VERSION 5.8 ;
BUSBITCHARS "[]" ;
DIVIDERCHAR "/" ;
UNITS
    DATABASE MICRONS 1000 ;
END UNITS

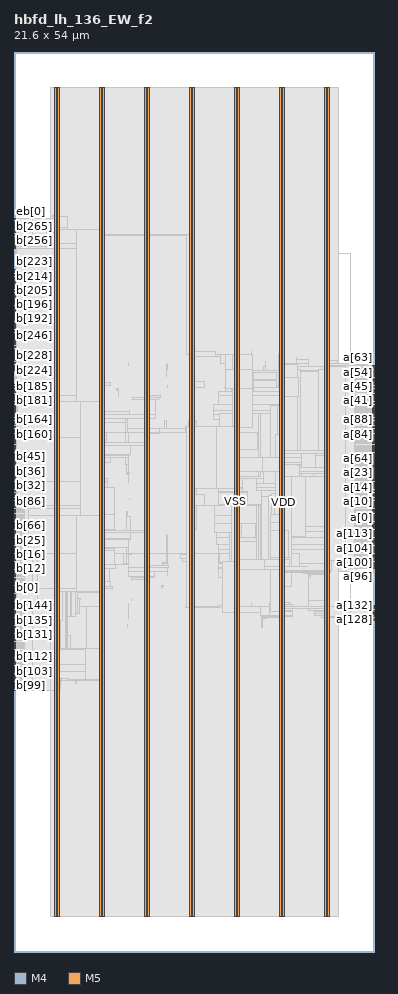
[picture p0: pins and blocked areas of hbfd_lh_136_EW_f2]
MACRO hbfd_lh_136_EW_f2
  FOREIGN hbfd_lh_136_EW_f2 0 0 ;
  CLASS BLOCK ;
  SIZE 21.6 BY 54 ;
  PIN a[0]
    DIRECTION INPUT ;
    USE SIGNAL ;
    PORT
      LAYER M4 ;
        RECT  21.516 26.064 21.6 26.088 ;
    END
  END a[0]
  PIN a[100]
    DIRECTION INPUT ;
    USE SIGNAL ;
    PORT
      LAYER M4 ;
        RECT  21.516 23.376 21.6 23.4 ;
    END
  END a[100]
  PIN a[101]
    DIRECTION INPUT ;
    USE SIGNAL ;
    PORT
      LAYER M4 ;
        RECT  21.516 23.472 21.6 23.496 ;
    END
  END a[101]
  PIN a[102]
    DIRECTION INPUT ;
    USE SIGNAL ;
    PORT
      LAYER M4 ;
        RECT  21.516 23.568 21.6 23.592 ;
    END
  END a[102]
  PIN a[103]
    DIRECTION INPUT ;
    USE SIGNAL ;
    PORT
      LAYER M4 ;
        RECT  21.516 23.664 21.6 23.688 ;
    END
  END a[103]
  PIN a[104]
    DIRECTION INPUT ;
    USE SIGNAL ;
    PORT
      LAYER M4 ;
        RECT  21.516 23.76 21.6 23.784 ;
    END
  END a[104]
  PIN a[105]
    DIRECTION INPUT ;
    USE SIGNAL ;
    PORT
      LAYER M4 ;
        RECT  21.516 23.856 21.6 23.88 ;
    END
  END a[105]
  PIN a[106]
    DIRECTION INPUT ;
    USE SIGNAL ;
    PORT
      LAYER M4 ;
        RECT  21.516 23.952 21.6 23.976 ;
    END
  END a[106]
  PIN a[107]
    DIRECTION INPUT ;
    USE SIGNAL ;
    PORT
      LAYER M4 ;
        RECT  21.516 24.048 21.6 24.072 ;
    END
  END a[107]
  PIN a[108]
    DIRECTION INPUT ;
    USE SIGNAL ;
    PORT
      LAYER M4 ;
        RECT  21.516 24.144 21.6 24.168 ;
    END
  END a[108]
  PIN a[109]
    DIRECTION INPUT ;
    USE SIGNAL ;
    PORT
      LAYER M4 ;
        RECT  21.516 24.24 21.6 24.264 ;
    END
  END a[109]
  PIN a[10]
    DIRECTION INPUT ;
    USE SIGNAL ;
    PORT
      LAYER M4 ;
        RECT  21.516 27.024 21.6 27.048 ;
    END
  END a[10]
  PIN a[110]
    DIRECTION INPUT ;
    USE SIGNAL ;
    PORT
      LAYER M4 ;
        RECT  21.516 24.336 21.6 24.36 ;
    END
  END a[110]
  PIN a[111]
    DIRECTION INPUT ;
    USE SIGNAL ;
    PORT
      LAYER M4 ;
        RECT  21.516 24.432 21.6 24.456 ;
    END
  END a[111]
  PIN a[112]
    DIRECTION INPUT ;
    USE SIGNAL ;
    PORT
      LAYER M4 ;
        RECT  21.516 24.528 21.6 24.552 ;
    END
  END a[112]
  PIN a[113]
    DIRECTION INPUT ;
    USE SIGNAL ;
    PORT
      LAYER M4 ;
        RECT  21.516 24.624 21.6 24.648 ;
    END
  END a[113]
  PIN a[114]
    DIRECTION INPUT ;
    USE SIGNAL ;
    PORT
      LAYER M4 ;
        RECT  21.516 24.72 21.6 24.744 ;
    END
  END a[114]
  PIN a[115]
    DIRECTION INPUT ;
    USE SIGNAL ;
    PORT
      LAYER M4 ;
        RECT  21.516 24.816 21.6 24.84 ;
    END
  END a[115]
  PIN a[116]
    DIRECTION INPUT ;
    USE SIGNAL ;
    PORT
      LAYER M4 ;
        RECT  21.516 24.912 21.6 24.936 ;
    END
  END a[116]
  PIN a[117]
    DIRECTION INPUT ;
    USE SIGNAL ;
    PORT
      LAYER M4 ;
        RECT  21.516 25.008 21.6 25.032 ;
    END
  END a[117]
  PIN a[118]
    DIRECTION INPUT ;
    USE SIGNAL ;
    PORT
      LAYER M4 ;
        RECT  21.516 25.104 21.6 25.128 ;
    END
  END a[118]
  PIN a[119]
    DIRECTION INPUT ;
    USE SIGNAL ;
    PORT
      LAYER M4 ;
        RECT  21.516 25.2 21.6 25.224 ;
    END
  END a[119]
  PIN a[11]
    DIRECTION INPUT ;
    USE SIGNAL ;
    PORT
      LAYER M4 ;
        RECT  21.516 27.12 21.6 27.144 ;
    END
  END a[11]
  PIN a[120]
    DIRECTION INPUT ;
    USE SIGNAL ;
    PORT
      LAYER M4 ;
        RECT  21.516 25.296 21.6 25.32 ;
    END
  END a[120]
  PIN a[121]
    DIRECTION INPUT ;
    USE SIGNAL ;
    PORT
      LAYER M4 ;
        RECT  21.516 25.392 21.6 25.416 ;
    END
  END a[121]
  PIN a[122]
    DIRECTION INPUT ;
    USE SIGNAL ;
    PORT
      LAYER M4 ;
        RECT  21.516 25.488 21.6 25.512 ;
    END
  END a[122]
  PIN a[123]
    DIRECTION INPUT ;
    USE SIGNAL ;
    PORT
      LAYER M4 ;
        RECT  21.516 25.584 21.6 25.608 ;
    END
  END a[123]
  PIN a[124]
    DIRECTION INPUT ;
    USE SIGNAL ;
    PORT
      LAYER M4 ;
        RECT  21.516 25.68 21.6 25.704 ;
    END
  END a[124]
  PIN a[125]
    DIRECTION INPUT ;
    USE SIGNAL ;
    PORT
      LAYER M4 ;
        RECT  21.516 25.776 21.6 25.8 ;
    END
  END a[125]
  PIN a[126]
    DIRECTION INPUT ;
    USE SIGNAL ;
    PORT
      LAYER M4 ;
        RECT  21.516 25.872 21.6 25.896 ;
    END
  END a[126]
  PIN a[127]
    DIRECTION INPUT ;
    USE SIGNAL ;
    PORT
      LAYER M4 ;
        RECT  21.516 25.968 21.6 25.992 ;
    END
  END a[127]
  PIN a[128]
    DIRECTION INPUT ;
    USE SIGNAL ;
    PORT
      LAYER M4 ;
        RECT  21.516 19.92 21.6 19.944 ;
    END
  END a[128]
  PIN a[129]
    DIRECTION INPUT ;
    USE SIGNAL ;
    PORT
      LAYER M4 ;
        RECT  21.516 20.016 21.6 20.04 ;
    END
  END a[129]
  PIN a[12]
    DIRECTION INPUT ;
    USE SIGNAL ;
    PORT
      LAYER M4 ;
        RECT  21.516 27.216 21.6 27.24 ;
    END
  END a[12]
  PIN a[130]
    DIRECTION INPUT ;
    USE SIGNAL ;
    PORT
      LAYER M4 ;
        RECT  21.516 20.112 21.6 20.136 ;
    END
  END a[130]
  PIN a[131]
    DIRECTION INPUT ;
    USE SIGNAL ;
    PORT
      LAYER M4 ;
        RECT  21.516 20.208 21.6 20.232 ;
    END
  END a[131]
  PIN a[132]
    DIRECTION INPUT ;
    USE SIGNAL ;
    PORT
      LAYER M4 ;
        RECT  21.516 20.304 21.6 20.328 ;
    END
  END a[132]
  PIN a[133]
    DIRECTION INPUT ;
    USE SIGNAL ;
    PORT
      LAYER M4 ;
        RECT  21.516 20.4 21.6 20.424 ;
    END
  END a[133]
  PIN a[134]
    DIRECTION INPUT ;
    USE SIGNAL ;
    PORT
      LAYER M4 ;
        RECT  21.516 20.496 21.6 20.52 ;
    END
  END a[134]
  PIN a[135]
    DIRECTION INPUT ;
    USE SIGNAL ;
    PORT
      LAYER M4 ;
        RECT  21.516 20.592 21.6 20.616 ;
    END
  END a[135]
  PIN a[13]
    DIRECTION INPUT ;
    USE SIGNAL ;
    PORT
      LAYER M4 ;
        RECT  21.516 27.312 21.6 27.336 ;
    END
  END a[13]
  PIN a[14]
    DIRECTION INPUT ;
    USE SIGNAL ;
    PORT
      LAYER M4 ;
        RECT  21.516 27.408 21.6 27.432 ;
    END
  END a[14]
  PIN a[15]
    DIRECTION INPUT ;
    USE SIGNAL ;
    PORT
      LAYER M4 ;
        RECT  21.516 27.504 21.6 27.528 ;
    END
  END a[15]
  PIN a[16]
    DIRECTION INPUT ;
    USE SIGNAL ;
    PORT
      LAYER M4 ;
        RECT  21.516 27.6 21.6 27.624 ;
    END
  END a[16]
  PIN a[17]
    DIRECTION INPUT ;
    USE SIGNAL ;
    PORT
      LAYER M4 ;
        RECT  21.516 27.696 21.6 27.72 ;
    END
  END a[17]
  PIN a[18]
    DIRECTION INPUT ;
    USE SIGNAL ;
    PORT
      LAYER M4 ;
        RECT  21.516 27.792 21.6 27.816 ;
    END
  END a[18]
  PIN a[19]
    DIRECTION INPUT ;
    USE SIGNAL ;
    PORT
      LAYER M4 ;
        RECT  21.516 27.888 21.6 27.912 ;
    END
  END a[19]
  PIN a[1]
    DIRECTION INPUT ;
    USE SIGNAL ;
    PORT
      LAYER M4 ;
        RECT  21.516 26.16 21.6 26.184 ;
    END
  END a[1]
  PIN a[20]
    DIRECTION INPUT ;
    USE SIGNAL ;
    PORT
      LAYER M4 ;
        RECT  21.516 27.984 21.6 28.008 ;
    END
  END a[20]
  PIN a[21]
    DIRECTION INPUT ;
    USE SIGNAL ;
    PORT
      LAYER M4 ;
        RECT  21.516 28.08 21.6 28.104 ;
    END
  END a[21]
  PIN a[22]
    DIRECTION INPUT ;
    USE SIGNAL ;
    PORT
      LAYER M4 ;
        RECT  21.516 28.176 21.6 28.2 ;
    END
  END a[22]
  PIN a[23]
    DIRECTION INPUT ;
    USE SIGNAL ;
    PORT
      LAYER M4 ;
        RECT  21.516 28.272 21.6 28.296 ;
    END
  END a[23]
  PIN a[24]
    DIRECTION INPUT ;
    USE SIGNAL ;
    PORT
      LAYER M4 ;
        RECT  21.516 28.368 21.6 28.392 ;
    END
  END a[24]
  PIN a[25]
    DIRECTION INPUT ;
    USE SIGNAL ;
    PORT
      LAYER M4 ;
        RECT  21.516 28.464 21.6 28.488 ;
    END
  END a[25]
  PIN a[26]
    DIRECTION INPUT ;
    USE SIGNAL ;
    PORT
      LAYER M4 ;
        RECT  21.516 28.56 21.6 28.584 ;
    END
  END a[26]
  PIN a[27]
    DIRECTION INPUT ;
    USE SIGNAL ;
    PORT
      LAYER M4 ;
        RECT  21.516 28.656 21.6 28.68 ;
    END
  END a[27]
  PIN a[28]
    DIRECTION INPUT ;
    USE SIGNAL ;
    PORT
      LAYER M4 ;
        RECT  21.516 28.752 21.6 28.776 ;
    END
  END a[28]
  PIN a[29]
    DIRECTION INPUT ;
    USE SIGNAL ;
    PORT
      LAYER M4 ;
        RECT  21.516 28.848 21.6 28.872 ;
    END
  END a[29]
  PIN a[2]
    DIRECTION INPUT ;
    USE SIGNAL ;
    PORT
      LAYER M4 ;
        RECT  21.516 26.256 21.6 26.28 ;
    END
  END a[2]
  PIN a[30]
    DIRECTION INPUT ;
    USE SIGNAL ;
    PORT
      LAYER M4 ;
        RECT  21.516 28.944 21.6 28.968 ;
    END
  END a[30]
  PIN a[31]
    DIRECTION INPUT ;
    USE SIGNAL ;
    PORT
      LAYER M4 ;
        RECT  21.516 29.04 21.6 29.064 ;
    END
  END a[31]
  PIN a[32]
    DIRECTION INPUT ;
    USE SIGNAL ;
    PORT
      LAYER M4 ;
        RECT  21.516 32.208 21.6 32.232 ;
    END
  END a[32]
  PIN a[33]
    DIRECTION INPUT ;
    USE SIGNAL ;
    PORT
      LAYER M4 ;
        RECT  21.516 32.304 21.6 32.328 ;
    END
  END a[33]
  PIN a[34]
    DIRECTION INPUT ;
    USE SIGNAL ;
    PORT
      LAYER M4 ;
        RECT  21.516 32.4 21.6 32.424 ;
    END
  END a[34]
  PIN a[35]
    DIRECTION INPUT ;
    USE SIGNAL ;
    PORT
      LAYER M4 ;
        RECT  21.516 32.496 21.6 32.52 ;
    END
  END a[35]
  PIN a[36]
    DIRECTION INPUT ;
    USE SIGNAL ;
    PORT
      LAYER M4 ;
        RECT  21.516 32.592 21.6 32.616 ;
    END
  END a[36]
  PIN a[37]
    DIRECTION INPUT ;
    USE SIGNAL ;
    PORT
      LAYER M4 ;
        RECT  21.516 32.688 21.6 32.712 ;
    END
  END a[37]
  PIN a[38]
    DIRECTION INPUT ;
    USE SIGNAL ;
    PORT
      LAYER M4 ;
        RECT  21.516 32.784 21.6 32.808 ;
    END
  END a[38]
  PIN a[39]
    DIRECTION INPUT ;
    USE SIGNAL ;
    PORT
      LAYER M4 ;
        RECT  21.516 32.88 21.6 32.904 ;
    END
  END a[39]
  PIN a[3]
    DIRECTION INPUT ;
    USE SIGNAL ;
    PORT
      LAYER M4 ;
        RECT  21.516 26.352 21.6 26.376 ;
    END
  END a[3]
  PIN a[40]
    DIRECTION INPUT ;
    USE SIGNAL ;
    PORT
      LAYER M4 ;
        RECT  21.516 32.976 21.6 33 ;
    END
  END a[40]
  PIN a[41]
    DIRECTION INPUT ;
    USE SIGNAL ;
    PORT
      LAYER M4 ;
        RECT  21.516 33.072 21.6 33.096 ;
    END
  END a[41]
  PIN a[42]
    DIRECTION INPUT ;
    USE SIGNAL ;
    PORT
      LAYER M4 ;
        RECT  21.516 33.168 21.6 33.192 ;
    END
  END a[42]
  PIN a[43]
    DIRECTION INPUT ;
    USE SIGNAL ;
    PORT
      LAYER M4 ;
        RECT  21.516 33.264 21.6 33.288 ;
    END
  END a[43]
  PIN a[44]
    DIRECTION INPUT ;
    USE SIGNAL ;
    PORT
      LAYER M4 ;
        RECT  21.516 33.36 21.6 33.384 ;
    END
  END a[44]
  PIN a[45]
    DIRECTION INPUT ;
    USE SIGNAL ;
    PORT
      LAYER M4 ;
        RECT  21.516 33.456 21.6 33.48 ;
    END
  END a[45]
  PIN a[46]
    DIRECTION INPUT ;
    USE SIGNAL ;
    PORT
      LAYER M4 ;
        RECT  21.516 33.552 21.6 33.576 ;
    END
  END a[46]
  PIN a[47]
    DIRECTION INPUT ;
    USE SIGNAL ;
    PORT
      LAYER M4 ;
        RECT  21.516 33.648 21.6 33.672 ;
    END
  END a[47]
  PIN a[48]
    DIRECTION INPUT ;
    USE SIGNAL ;
    PORT
      LAYER M4 ;
        RECT  21.516 33.744 21.6 33.768 ;
    END
  END a[48]
  PIN a[49]
    DIRECTION INPUT ;
    USE SIGNAL ;
    PORT
      LAYER M4 ;
        RECT  21.516 33.84 21.6 33.864 ;
    END
  END a[49]
  PIN a[4]
    DIRECTION INPUT ;
    USE SIGNAL ;
    PORT
      LAYER M4 ;
        RECT  21.516 26.448 21.6 26.472 ;
    END
  END a[4]
  PIN a[50]
    DIRECTION INPUT ;
    USE SIGNAL ;
    PORT
      LAYER M4 ;
        RECT  21.516 33.936 21.6 33.96 ;
    END
  END a[50]
  PIN a[51]
    DIRECTION INPUT ;
    USE SIGNAL ;
    PORT
      LAYER M4 ;
        RECT  21.516 34.032 21.6 34.056 ;
    END
  END a[51]
  PIN a[52]
    DIRECTION INPUT ;
    USE SIGNAL ;
    PORT
      LAYER M4 ;
        RECT  21.516 34.128 21.6 34.152 ;
    END
  END a[52]
  PIN a[53]
    DIRECTION INPUT ;
    USE SIGNAL ;
    PORT
      LAYER M4 ;
        RECT  21.516 34.224 21.6 34.248 ;
    END
  END a[53]
  PIN a[54]
    DIRECTION INPUT ;
    USE SIGNAL ;
    PORT
      LAYER M4 ;
        RECT  21.516 34.32 21.6 34.344 ;
    END
  END a[54]
  PIN a[55]
    DIRECTION INPUT ;
    USE SIGNAL ;
    PORT
      LAYER M4 ;
        RECT  21.516 34.416 21.6 34.44 ;
    END
  END a[55]
  PIN a[56]
    DIRECTION INPUT ;
    USE SIGNAL ;
    PORT
      LAYER M4 ;
        RECT  21.516 34.512 21.6 34.536 ;
    END
  END a[56]
  PIN a[57]
    DIRECTION INPUT ;
    USE SIGNAL ;
    PORT
      LAYER M4 ;
        RECT  21.516 34.608 21.6 34.632 ;
    END
  END a[57]
  PIN a[58]
    DIRECTION INPUT ;
    USE SIGNAL ;
    PORT
      LAYER M4 ;
        RECT  21.516 34.704 21.6 34.728 ;
    END
  END a[58]
  PIN a[59]
    DIRECTION INPUT ;
    USE SIGNAL ;
    PORT
      LAYER M4 ;
        RECT  21.516 34.8 21.6 34.824 ;
    END
  END a[59]
  PIN a[5]
    DIRECTION INPUT ;
    USE SIGNAL ;
    PORT
      LAYER M4 ;
        RECT  21.516 26.544 21.6 26.568 ;
    END
  END a[5]
  PIN a[60]
    DIRECTION INPUT ;
    USE SIGNAL ;
    PORT
      LAYER M4 ;
        RECT  21.516 34.896 21.6 34.92 ;
    END
  END a[60]
  PIN a[61]
    DIRECTION INPUT ;
    USE SIGNAL ;
    PORT
      LAYER M4 ;
        RECT  21.516 34.992 21.6 35.016 ;
    END
  END a[61]
  PIN a[62]
    DIRECTION INPUT ;
    USE SIGNAL ;
    PORT
      LAYER M4 ;
        RECT  21.516 35.088 21.6 35.112 ;
    END
  END a[62]
  PIN a[63]
    DIRECTION INPUT ;
    USE SIGNAL ;
    PORT
      LAYER M4 ;
        RECT  21.516 35.184 21.6 35.208 ;
    END
  END a[63]
  PIN a[64]
    DIRECTION INPUT ;
    USE SIGNAL ;
    PORT
      LAYER M4 ;
        RECT  21.516 29.136 21.6 29.16 ;
    END
  END a[64]
  PIN a[65]
    DIRECTION INPUT ;
    USE SIGNAL ;
    PORT
      LAYER M4 ;
        RECT  21.516 29.232 21.6 29.256 ;
    END
  END a[65]
  PIN a[66]
    DIRECTION INPUT ;
    USE SIGNAL ;
    PORT
      LAYER M4 ;
        RECT  21.516 29.328 21.6 29.352 ;
    END
  END a[66]
  PIN a[67]
    DIRECTION INPUT ;
    USE SIGNAL ;
    PORT
      LAYER M4 ;
        RECT  21.516 29.424 21.6 29.448 ;
    END
  END a[67]
  PIN a[68]
    DIRECTION INPUT ;
    USE SIGNAL ;
    PORT
      LAYER M4 ;
        RECT  21.516 29.52 21.6 29.544 ;
    END
  END a[68]
  PIN a[69]
    DIRECTION INPUT ;
    USE SIGNAL ;
    PORT
      LAYER M4 ;
        RECT  21.516 29.616 21.6 29.64 ;
    END
  END a[69]
  PIN a[6]
    DIRECTION INPUT ;
    USE SIGNAL ;
    PORT
      LAYER M4 ;
        RECT  21.516 26.64 21.6 26.664 ;
    END
  END a[6]
  PIN a[70]
    DIRECTION INPUT ;
    USE SIGNAL ;
    PORT
      LAYER M4 ;
        RECT  21.516 29.712 21.6 29.736 ;
    END
  END a[70]
  PIN a[71]
    DIRECTION INPUT ;
    USE SIGNAL ;
    PORT
      LAYER M4 ;
        RECT  21.516 29.808 21.6 29.832 ;
    END
  END a[71]
  PIN a[72]
    DIRECTION INPUT ;
    USE SIGNAL ;
    PORT
      LAYER M4 ;
        RECT  21.516 29.904 21.6 29.928 ;
    END
  END a[72]
  PIN a[73]
    DIRECTION INPUT ;
    USE SIGNAL ;
    PORT
      LAYER M4 ;
        RECT  21.516 30 21.6 30.024 ;
    END
  END a[73]
  PIN a[74]
    DIRECTION INPUT ;
    USE SIGNAL ;
    PORT
      LAYER M4 ;
        RECT  21.516 30.096 21.6 30.12 ;
    END
  END a[74]
  PIN a[75]
    DIRECTION INPUT ;
    USE SIGNAL ;
    PORT
      LAYER M4 ;
        RECT  21.516 30.192 21.6 30.216 ;
    END
  END a[75]
  PIN a[76]
    DIRECTION INPUT ;
    USE SIGNAL ;
    PORT
      LAYER M4 ;
        RECT  21.516 30.288 21.6 30.312 ;
    END
  END a[76]
  PIN a[77]
    DIRECTION INPUT ;
    USE SIGNAL ;
    PORT
      LAYER M4 ;
        RECT  21.516 30.384 21.6 30.408 ;
    END
  END a[77]
  PIN a[78]
    DIRECTION INPUT ;
    USE SIGNAL ;
    PORT
      LAYER M4 ;
        RECT  21.516 30.48 21.6 30.504 ;
    END
  END a[78]
  PIN a[79]
    DIRECTION INPUT ;
    USE SIGNAL ;
    PORT
      LAYER M4 ;
        RECT  21.516 30.576 21.6 30.6 ;
    END
  END a[79]
  PIN a[7]
    DIRECTION INPUT ;
    USE SIGNAL ;
    PORT
      LAYER M4 ;
        RECT  21.516 26.736 21.6 26.76 ;
    END
  END a[7]
  PIN a[80]
    DIRECTION INPUT ;
    USE SIGNAL ;
    PORT
      LAYER M4 ;
        RECT  21.516 30.672 21.6 30.696 ;
    END
  END a[80]
  PIN a[81]
    DIRECTION INPUT ;
    USE SIGNAL ;
    PORT
      LAYER M4 ;
        RECT  21.516 30.768 21.6 30.792 ;
    END
  END a[81]
  PIN a[82]
    DIRECTION INPUT ;
    USE SIGNAL ;
    PORT
      LAYER M4 ;
        RECT  21.516 30.864 21.6 30.888 ;
    END
  END a[82]
  PIN a[83]
    DIRECTION INPUT ;
    USE SIGNAL ;
    PORT
      LAYER M4 ;
        RECT  21.516 30.96 21.6 30.984 ;
    END
  END a[83]
  PIN a[84]
    DIRECTION INPUT ;
    USE SIGNAL ;
    PORT
      LAYER M4 ;
        RECT  21.516 31.056 21.6 31.08 ;
    END
  END a[84]
  PIN a[85]
    DIRECTION INPUT ;
    USE SIGNAL ;
    PORT
      LAYER M4 ;
        RECT  21.516 31.152 21.6 31.176 ;
    END
  END a[85]
  PIN a[86]
    DIRECTION INPUT ;
    USE SIGNAL ;
    PORT
      LAYER M4 ;
        RECT  21.516 31.248 21.6 31.272 ;
    END
  END a[86]
  PIN a[87]
    DIRECTION INPUT ;
    USE SIGNAL ;
    PORT
      LAYER M4 ;
        RECT  21.516 31.344 21.6 31.368 ;
    END
  END a[87]
  PIN a[88]
    DIRECTION INPUT ;
    USE SIGNAL ;
    PORT
      LAYER M4 ;
        RECT  21.516 31.44 21.6 31.464 ;
    END
  END a[88]
  PIN a[89]
    DIRECTION INPUT ;
    USE SIGNAL ;
    PORT
      LAYER M4 ;
        RECT  21.516 31.536 21.6 31.56 ;
    END
  END a[89]
  PIN a[8]
    DIRECTION INPUT ;
    USE SIGNAL ;
    PORT
      LAYER M4 ;
        RECT  21.516 26.832 21.6 26.856 ;
    END
  END a[8]
  PIN a[90]
    DIRECTION INPUT ;
    USE SIGNAL ;
    PORT
      LAYER M4 ;
        RECT  21.516 31.632 21.6 31.656 ;
    END
  END a[90]
  PIN a[91]
    DIRECTION INPUT ;
    USE SIGNAL ;
    PORT
      LAYER M4 ;
        RECT  21.516 31.728 21.6 31.752 ;
    END
  END a[91]
  PIN a[92]
    DIRECTION INPUT ;
    USE SIGNAL ;
    PORT
      LAYER M4 ;
        RECT  21.516 31.824 21.6 31.848 ;
    END
  END a[92]
  PIN a[93]
    DIRECTION INPUT ;
    USE SIGNAL ;
    PORT
      LAYER M4 ;
        RECT  21.516 31.92 21.6 31.944 ;
    END
  END a[93]
  PIN a[94]
    DIRECTION INPUT ;
    USE SIGNAL ;
    PORT
      LAYER M4 ;
        RECT  21.516 32.016 21.6 32.04 ;
    END
  END a[94]
  PIN a[95]
    DIRECTION INPUT ;
    USE SIGNAL ;
    PORT
      LAYER M4 ;
        RECT  21.516 32.112 21.6 32.136 ;
    END
  END a[95]
  PIN a[96]
    DIRECTION INPUT ;
    USE SIGNAL ;
    PORT
      LAYER M4 ;
        RECT  21.516 22.992 21.6 23.016 ;
    END
  END a[96]
  PIN a[97]
    DIRECTION INPUT ;
    USE SIGNAL ;
    PORT
      LAYER M4 ;
        RECT  21.516 23.088 21.6 23.112 ;
    END
  END a[97]
  PIN a[98]
    DIRECTION INPUT ;
    USE SIGNAL ;
    PORT
      LAYER M4 ;
        RECT  21.516 23.184 21.6 23.208 ;
    END
  END a[98]
  PIN a[99]
    DIRECTION INPUT ;
    USE SIGNAL ;
    PORT
      LAYER M4 ;
        RECT  21.516 23.28 21.6 23.304 ;
    END
  END a[99]
  PIN a[9]
    DIRECTION INPUT ;
    USE SIGNAL ;
    PORT
      LAYER M4 ;
        RECT  21.516 26.928 21.6 26.952 ;
    END
  END a[9]
  PIN b[0]
    DIRECTION OUTPUT ;
    USE SIGNAL ;
    PORT
      LAYER M4 ;
        RECT  0 21.84 0.084 21.864 ;
    END
  END b[0]
  PIN b[100]
    DIRECTION OUTPUT ;
    USE SIGNAL ;
    PORT
      LAYER M4 ;
        RECT  0 16.08 0.084 16.104 ;
    END
  END b[100]
  PIN b[101]
    DIRECTION OUTPUT ;
    USE SIGNAL ;
    PORT
      LAYER M4 ;
        RECT  0 16.176 0.084 16.2 ;
    END
  END b[101]
  PIN b[102]
    DIRECTION OUTPUT ;
    USE SIGNAL ;
    PORT
      LAYER M4 ;
        RECT  0 16.272 0.084 16.296 ;
    END
  END b[102]
  PIN b[103]
    DIRECTION OUTPUT ;
    USE SIGNAL ;
    PORT
      LAYER M4 ;
        RECT  0 16.368 0.084 16.392 ;
    END
  END b[103]
  PIN b[104]
    DIRECTION OUTPUT ;
    USE SIGNAL ;
    PORT
      LAYER M4 ;
        RECT  0 16.464 0.084 16.488 ;
    END
  END b[104]
  PIN b[105]
    DIRECTION OUTPUT ;
    USE SIGNAL ;
    PORT
      LAYER M4 ;
        RECT  0 16.56 0.084 16.584 ;
    END
  END b[105]
  PIN b[106]
    DIRECTION OUTPUT ;
    USE SIGNAL ;
    PORT
      LAYER M4 ;
        RECT  0 16.656 0.084 16.68 ;
    END
  END b[106]
  PIN b[107]
    DIRECTION OUTPUT ;
    USE SIGNAL ;
    PORT
      LAYER M4 ;
        RECT  0 16.752 0.084 16.776 ;
    END
  END b[107]
  PIN b[108]
    DIRECTION OUTPUT ;
    USE SIGNAL ;
    PORT
      LAYER M4 ;
        RECT  0 16.848 0.084 16.872 ;
    END
  END b[108]
  PIN b[109]
    DIRECTION OUTPUT ;
    USE SIGNAL ;
    PORT
      LAYER M4 ;
        RECT  0 16.944 0.084 16.968 ;
    END
  END b[109]
  PIN b[10]
    DIRECTION OUTPUT ;
    USE SIGNAL ;
    PORT
      LAYER M4 ;
        RECT  0 22.8 0.084 22.824 ;
    END
  END b[10]
  PIN b[110]
    DIRECTION OUTPUT ;
    USE SIGNAL ;
    PORT
      LAYER M4 ;
        RECT  0 17.04 0.084 17.064 ;
    END
  END b[110]
  PIN b[111]
    DIRECTION OUTPUT ;
    USE SIGNAL ;
    PORT
      LAYER M4 ;
        RECT  0 17.136 0.084 17.16 ;
    END
  END b[111]
  PIN b[112]
    DIRECTION OUTPUT ;
    USE SIGNAL ;
    PORT
      LAYER M4 ;
        RECT  0 17.232 0.084 17.256 ;
    END
  END b[112]
  PIN b[113]
    DIRECTION OUTPUT ;
    USE SIGNAL ;
    PORT
      LAYER M4 ;
        RECT  0 17.328 0.084 17.352 ;
    END
  END b[113]
  PIN b[114]
    DIRECTION OUTPUT ;
    USE SIGNAL ;
    PORT
      LAYER M4 ;
        RECT  0 17.424 0.084 17.448 ;
    END
  END b[114]
  PIN b[115]
    DIRECTION OUTPUT ;
    USE SIGNAL ;
    PORT
      LAYER M4 ;
        RECT  0 17.52 0.084 17.544 ;
    END
  END b[115]
  PIN b[116]
    DIRECTION OUTPUT ;
    USE SIGNAL ;
    PORT
      LAYER M4 ;
        RECT  0 17.616 0.084 17.64 ;
    END
  END b[116]
  PIN b[117]
    DIRECTION OUTPUT ;
    USE SIGNAL ;
    PORT
      LAYER M4 ;
        RECT  0 17.712 0.084 17.736 ;
    END
  END b[117]
  PIN b[118]
    DIRECTION OUTPUT ;
    USE SIGNAL ;
    PORT
      LAYER M4 ;
        RECT  0 17.808 0.084 17.832 ;
    END
  END b[118]
  PIN b[119]
    DIRECTION OUTPUT ;
    USE SIGNAL ;
    PORT
      LAYER M4 ;
        RECT  0 17.904 0.084 17.928 ;
    END
  END b[119]
  PIN b[11]
    DIRECTION OUTPUT ;
    USE SIGNAL ;
    PORT
      LAYER M4 ;
        RECT  0 22.896 0.084 22.92 ;
    END
  END b[11]
  PIN b[120]
    DIRECTION OUTPUT ;
    USE SIGNAL ;
    PORT
      LAYER M4 ;
        RECT  0 18 0.084 18.024 ;
    END
  END b[120]
  PIN b[121]
    DIRECTION OUTPUT ;
    USE SIGNAL ;
    PORT
      LAYER M4 ;
        RECT  0 18.096 0.084 18.12 ;
    END
  END b[121]
  PIN b[122]
    DIRECTION OUTPUT ;
    USE SIGNAL ;
    PORT
      LAYER M4 ;
        RECT  0 18.192 0.084 18.216 ;
    END
  END b[122]
  PIN b[123]
    DIRECTION OUTPUT ;
    USE SIGNAL ;
    PORT
      LAYER M4 ;
        RECT  0 18.288 0.084 18.312 ;
    END
  END b[123]
  PIN b[124]
    DIRECTION OUTPUT ;
    USE SIGNAL ;
    PORT
      LAYER M4 ;
        RECT  0 18.384 0.084 18.408 ;
    END
  END b[124]
  PIN b[125]
    DIRECTION OUTPUT ;
    USE SIGNAL ;
    PORT
      LAYER M4 ;
        RECT  0 18.48 0.084 18.504 ;
    END
  END b[125]
  PIN b[126]
    DIRECTION OUTPUT ;
    USE SIGNAL ;
    PORT
      LAYER M4 ;
        RECT  0 18.576 0.084 18.6 ;
    END
  END b[126]
  PIN b[127]
    DIRECTION OUTPUT ;
    USE SIGNAL ;
    PORT
      LAYER M4 ;
        RECT  0 18.672 0.084 18.696 ;
    END
  END b[127]
  PIN b[128]
    DIRECTION OUTPUT ;
    USE SIGNAL ;
    PORT
      LAYER M4 ;
        RECT  0 18.768 0.084 18.792 ;
    END
  END b[128]
  PIN b[129]
    DIRECTION OUTPUT ;
    USE SIGNAL ;
    PORT
      LAYER M4 ;
        RECT  0 18.864 0.084 18.888 ;
    END
  END b[129]
  PIN b[12]
    DIRECTION OUTPUT ;
    USE SIGNAL ;
    PORT
      LAYER M4 ;
        RECT  0 22.992 0.084 23.016 ;
    END
  END b[12]
  PIN b[130]
    DIRECTION OUTPUT ;
    USE SIGNAL ;
    PORT
      LAYER M4 ;
        RECT  0 18.96 0.084 18.984 ;
    END
  END b[130]
  PIN b[131]
    DIRECTION OUTPUT ;
    USE SIGNAL ;
    PORT
      LAYER M4 ;
        RECT  0 19.056 0.084 19.08 ;
    END
  END b[131]
  PIN b[132]
    DIRECTION OUTPUT ;
    USE SIGNAL ;
    PORT
      LAYER M4 ;
        RECT  0 19.152 0.084 19.176 ;
    END
  END b[132]
  PIN b[133]
    DIRECTION OUTPUT ;
    USE SIGNAL ;
    PORT
      LAYER M4 ;
        RECT  0 19.248 0.084 19.272 ;
    END
  END b[133]
  PIN b[134]
    DIRECTION OUTPUT ;
    USE SIGNAL ;
    PORT
      LAYER M4 ;
        RECT  0 19.344 0.084 19.368 ;
    END
  END b[134]
  PIN b[135]
    DIRECTION OUTPUT ;
    USE SIGNAL ;
    PORT
      LAYER M4 ;
        RECT  0 19.44 0.084 19.464 ;
    END
  END b[135]
  PIN b[136]
    DIRECTION OUTPUT ;
    USE SIGNAL ;
    PORT
      LAYER M4 ;
        RECT  0 19.536 0.084 19.56 ;
    END
  END b[136]
  PIN b[137]
    DIRECTION OUTPUT ;
    USE SIGNAL ;
    PORT
      LAYER M4 ;
        RECT  0 19.632 0.084 19.656 ;
    END
  END b[137]
  PIN b[138]
    DIRECTION OUTPUT ;
    USE SIGNAL ;
    PORT
      LAYER M4 ;
        RECT  0 19.728 0.084 19.752 ;
    END
  END b[138]
  PIN b[139]
    DIRECTION OUTPUT ;
    USE SIGNAL ;
    PORT
      LAYER M4 ;
        RECT  0 19.824 0.084 19.848 ;
    END
  END b[139]
  PIN b[13]
    DIRECTION OUTPUT ;
    USE SIGNAL ;
    PORT
      LAYER M4 ;
        RECT  0 23.088 0.084 23.112 ;
    END
  END b[13]
  PIN b[140]
    DIRECTION OUTPUT ;
    USE SIGNAL ;
    PORT
      LAYER M4 ;
        RECT  0 19.92 0.084 19.944 ;
    END
  END b[140]
  PIN b[141]
    DIRECTION OUTPUT ;
    USE SIGNAL ;
    PORT
      LAYER M4 ;
        RECT  0 20.016 0.084 20.04 ;
    END
  END b[141]
  PIN b[142]
    DIRECTION OUTPUT ;
    USE SIGNAL ;
    PORT
      LAYER M4 ;
        RECT  0 20.112 0.084 20.136 ;
    END
  END b[142]
  PIN b[143]
    DIRECTION OUTPUT ;
    USE SIGNAL ;
    PORT
      LAYER M4 ;
        RECT  0 20.208 0.084 20.232 ;
    END
  END b[143]
  PIN b[144]
    DIRECTION OUTPUT ;
    USE SIGNAL ;
    PORT
      LAYER M4 ;
        RECT  0 20.304 0.084 20.328 ;
    END
  END b[144]
  PIN b[145]
    DIRECTION OUTPUT ;
    USE SIGNAL ;
    PORT
      LAYER M4 ;
        RECT  0 20.4 0.084 20.424 ;
    END
  END b[145]
  PIN b[146]
    DIRECTION OUTPUT ;
    USE SIGNAL ;
    PORT
      LAYER M4 ;
        RECT  0 20.496 0.084 20.52 ;
    END
  END b[146]
  PIN b[147]
    DIRECTION OUTPUT ;
    USE SIGNAL ;
    PORT
      LAYER M4 ;
        RECT  0 20.592 0.084 20.616 ;
    END
  END b[147]
  PIN b[148]
    DIRECTION OUTPUT ;
    USE SIGNAL ;
    PORT
      LAYER M4 ;
        RECT  0 20.688 0.084 20.712 ;
    END
  END b[148]
  PIN b[149]
    DIRECTION OUTPUT ;
    USE SIGNAL ;
    PORT
      LAYER M4 ;
        RECT  0 20.784 0.084 20.808 ;
    END
  END b[149]
  PIN b[14]
    DIRECTION OUTPUT ;
    USE SIGNAL ;
    PORT
      LAYER M4 ;
        RECT  0 23.184 0.084 23.208 ;
    END
  END b[14]
  PIN b[150]
    DIRECTION OUTPUT ;
    USE SIGNAL ;
    PORT
      LAYER M4 ;
        RECT  0 20.88 0.084 20.904 ;
    END
  END b[150]
  PIN b[151]
    DIRECTION OUTPUT ;
    USE SIGNAL ;
    PORT
      LAYER M4 ;
        RECT  0 20.976 0.084 21 ;
    END
  END b[151]
  PIN b[152]
    DIRECTION OUTPUT ;
    USE SIGNAL ;
    PORT
      LAYER M4 ;
        RECT  0 21.072 0.084 21.096 ;
    END
  END b[152]
  PIN b[153]
    DIRECTION OUTPUT ;
    USE SIGNAL ;
    PORT
      LAYER M4 ;
        RECT  0 21.168 0.084 21.192 ;
    END
  END b[153]
  PIN b[154]
    DIRECTION OUTPUT ;
    USE SIGNAL ;
    PORT
      LAYER M4 ;
        RECT  0 21.264 0.084 21.288 ;
    END
  END b[154]
  PIN b[155]
    DIRECTION OUTPUT ;
    USE SIGNAL ;
    PORT
      LAYER M4 ;
        RECT  0 21.36 0.084 21.384 ;
    END
  END b[155]
  PIN b[156]
    DIRECTION OUTPUT ;
    USE SIGNAL ;
    PORT
      LAYER M4 ;
        RECT  0 21.456 0.084 21.48 ;
    END
  END b[156]
  PIN b[157]
    DIRECTION OUTPUT ;
    USE SIGNAL ;
    PORT
      LAYER M4 ;
        RECT  0 21.552 0.084 21.576 ;
    END
  END b[157]
  PIN b[158]
    DIRECTION OUTPUT ;
    USE SIGNAL ;
    PORT
      LAYER M4 ;
        RECT  0 21.648 0.084 21.672 ;
    END
  END b[158]
  PIN b[159]
    DIRECTION OUTPUT ;
    USE SIGNAL ;
    PORT
      LAYER M4 ;
        RECT  0 21.744 0.084 21.768 ;
    END
  END b[159]
  PIN b[15]
    DIRECTION OUTPUT ;
    USE SIGNAL ;
    PORT
      LAYER M4 ;
        RECT  0 23.28 0.084 23.304 ;
    END
  END b[15]
  PIN b[160]
    DIRECTION OUTPUT ;
    USE SIGNAL ;
    PORT
      LAYER M4 ;
        RECT  0 31.056 0.084 31.08 ;
    END
  END b[160]
  PIN b[161]
    DIRECTION OUTPUT ;
    USE SIGNAL ;
    PORT
      LAYER M4 ;
        RECT  0 31.152 0.084 31.176 ;
    END
  END b[161]
  PIN b[162]
    DIRECTION OUTPUT ;
    USE SIGNAL ;
    PORT
      LAYER M4 ;
        RECT  0 31.248 0.084 31.272 ;
    END
  END b[162]
  PIN b[163]
    DIRECTION OUTPUT ;
    USE SIGNAL ;
    PORT
      LAYER M4 ;
        RECT  0 31.344 0.084 31.368 ;
    END
  END b[163]
  PIN b[164]
    DIRECTION OUTPUT ;
    USE SIGNAL ;
    PORT
      LAYER M4 ;
        RECT  0 31.44 0.084 31.464 ;
    END
  END b[164]
  PIN b[165]
    DIRECTION OUTPUT ;
    USE SIGNAL ;
    PORT
      LAYER M4 ;
        RECT  0 31.536 0.084 31.56 ;
    END
  END b[165]
  PIN b[166]
    DIRECTION OUTPUT ;
    USE SIGNAL ;
    PORT
      LAYER M4 ;
        RECT  0 31.632 0.084 31.656 ;
    END
  END b[166]
  PIN b[167]
    DIRECTION OUTPUT ;
    USE SIGNAL ;
    PORT
      LAYER M4 ;
        RECT  0 31.728 0.084 31.752 ;
    END
  END b[167]
  PIN b[168]
    DIRECTION OUTPUT ;
    USE SIGNAL ;
    PORT
      LAYER M4 ;
        RECT  0 31.824 0.084 31.848 ;
    END
  END b[168]
  PIN b[169]
    DIRECTION OUTPUT ;
    USE SIGNAL ;
    PORT
      LAYER M4 ;
        RECT  0 31.92 0.084 31.944 ;
    END
  END b[169]
  PIN b[16]
    DIRECTION OUTPUT ;
    USE SIGNAL ;
    PORT
      LAYER M4 ;
        RECT  0 23.376 0.084 23.4 ;
    END
  END b[16]
  PIN b[170]
    DIRECTION OUTPUT ;
    USE SIGNAL ;
    PORT
      LAYER M4 ;
        RECT  0 32.016 0.084 32.04 ;
    END
  END b[170]
  PIN b[171]
    DIRECTION OUTPUT ;
    USE SIGNAL ;
    PORT
      LAYER M4 ;
        RECT  0 32.112 0.084 32.136 ;
    END
  END b[171]
  PIN b[172]
    DIRECTION OUTPUT ;
    USE SIGNAL ;
    PORT
      LAYER M4 ;
        RECT  0 32.208 0.084 32.232 ;
    END
  END b[172]
  PIN b[173]
    DIRECTION OUTPUT ;
    USE SIGNAL ;
    PORT
      LAYER M4 ;
        RECT  0 32.304 0.084 32.328 ;
    END
  END b[173]
  PIN b[174]
    DIRECTION OUTPUT ;
    USE SIGNAL ;
    PORT
      LAYER M4 ;
        RECT  0 32.4 0.084 32.424 ;
    END
  END b[174]
  PIN b[175]
    DIRECTION OUTPUT ;
    USE SIGNAL ;
    PORT
      LAYER M4 ;
        RECT  0 32.496 0.084 32.52 ;
    END
  END b[175]
  PIN b[176]
    DIRECTION OUTPUT ;
    USE SIGNAL ;
    PORT
      LAYER M4 ;
        RECT  0 32.592 0.084 32.616 ;
    END
  END b[176]
  PIN b[177]
    DIRECTION OUTPUT ;
    USE SIGNAL ;
    PORT
      LAYER M4 ;
        RECT  0 32.688 0.084 32.712 ;
    END
  END b[177]
  PIN b[178]
    DIRECTION OUTPUT ;
    USE SIGNAL ;
    PORT
      LAYER M4 ;
        RECT  0 32.784 0.084 32.808 ;
    END
  END b[178]
  PIN b[179]
    DIRECTION OUTPUT ;
    USE SIGNAL ;
    PORT
      LAYER M4 ;
        RECT  0 32.88 0.084 32.904 ;
    END
  END b[179]
  PIN b[17]
    DIRECTION OUTPUT ;
    USE SIGNAL ;
    PORT
      LAYER M4 ;
        RECT  0 23.472 0.084 23.496 ;
    END
  END b[17]
  PIN b[180]
    DIRECTION OUTPUT ;
    USE SIGNAL ;
    PORT
      LAYER M4 ;
        RECT  0 32.976 0.084 33 ;
    END
  END b[180]
  PIN b[181]
    DIRECTION OUTPUT ;
    USE SIGNAL ;
    PORT
      LAYER M4 ;
        RECT  0 33.072 0.084 33.096 ;
    END
  END b[181]
  PIN b[182]
    DIRECTION OUTPUT ;
    USE SIGNAL ;
    PORT
      LAYER M4 ;
        RECT  0 33.168 0.084 33.192 ;
    END
  END b[182]
  PIN b[183]
    DIRECTION OUTPUT ;
    USE SIGNAL ;
    PORT
      LAYER M4 ;
        RECT  0 33.264 0.084 33.288 ;
    END
  END b[183]
  PIN b[184]
    DIRECTION OUTPUT ;
    USE SIGNAL ;
    PORT
      LAYER M4 ;
        RECT  0 33.36 0.084 33.384 ;
    END
  END b[184]
  PIN b[185]
    DIRECTION OUTPUT ;
    USE SIGNAL ;
    PORT
      LAYER M4 ;
        RECT  0 33.456 0.084 33.48 ;
    END
  END b[185]
  PIN b[186]
    DIRECTION OUTPUT ;
    USE SIGNAL ;
    PORT
      LAYER M4 ;
        RECT  0 33.552 0.084 33.576 ;
    END
  END b[186]
  PIN b[187]
    DIRECTION OUTPUT ;
    USE SIGNAL ;
    PORT
      LAYER M4 ;
        RECT  0 33.648 0.084 33.672 ;
    END
  END b[187]
  PIN b[188]
    DIRECTION OUTPUT ;
    USE SIGNAL ;
    PORT
      LAYER M4 ;
        RECT  0 33.744 0.084 33.768 ;
    END
  END b[188]
  PIN b[189]
    DIRECTION OUTPUT ;
    USE SIGNAL ;
    PORT
      LAYER M4 ;
        RECT  0 33.84 0.084 33.864 ;
    END
  END b[189]
  PIN b[18]
    DIRECTION OUTPUT ;
    USE SIGNAL ;
    PORT
      LAYER M4 ;
        RECT  0 23.568 0.084 23.592 ;
    END
  END b[18]
  PIN b[190]
    DIRECTION OUTPUT ;
    USE SIGNAL ;
    PORT
      LAYER M4 ;
        RECT  0 33.936 0.084 33.96 ;
    END
  END b[190]
  PIN b[191]
    DIRECTION OUTPUT ;
    USE SIGNAL ;
    PORT
      LAYER M4 ;
        RECT  0 34.032 0.084 34.056 ;
    END
  END b[191]
  PIN b[192]
    DIRECTION OUTPUT ;
    USE SIGNAL ;
    PORT
      LAYER M4 ;
        RECT  0 37.968 0.084 37.992 ;
    END
  END b[192]
  PIN b[193]
    DIRECTION OUTPUT ;
    USE SIGNAL ;
    PORT
      LAYER M4 ;
        RECT  0 38.064 0.084 38.088 ;
    END
  END b[193]
  PIN b[194]
    DIRECTION OUTPUT ;
    USE SIGNAL ;
    PORT
      LAYER M4 ;
        RECT  0 38.16 0.084 38.184 ;
    END
  END b[194]
  PIN b[195]
    DIRECTION OUTPUT ;
    USE SIGNAL ;
    PORT
      LAYER M4 ;
        RECT  0 38.256 0.084 38.28 ;
    END
  END b[195]
  PIN b[196]
    DIRECTION OUTPUT ;
    USE SIGNAL ;
    PORT
      LAYER M4 ;
        RECT  0 38.352 0.084 38.376 ;
    END
  END b[196]
  PIN b[197]
    DIRECTION OUTPUT ;
    USE SIGNAL ;
    PORT
      LAYER M4 ;
        RECT  0 38.448 0.084 38.472 ;
    END
  END b[197]
  PIN b[198]
    DIRECTION OUTPUT ;
    USE SIGNAL ;
    PORT
      LAYER M4 ;
        RECT  0 38.544 0.084 38.568 ;
    END
  END b[198]
  PIN b[199]
    DIRECTION OUTPUT ;
    USE SIGNAL ;
    PORT
      LAYER M4 ;
        RECT  0 38.64 0.084 38.664 ;
    END
  END b[199]
  PIN b[19]
    DIRECTION OUTPUT ;
    USE SIGNAL ;
    PORT
      LAYER M4 ;
        RECT  0 23.664 0.084 23.688 ;
    END
  END b[19]
  PIN b[1]
    DIRECTION OUTPUT ;
    USE SIGNAL ;
    PORT
      LAYER M4 ;
        RECT  0 21.936 0.084 21.96 ;
    END
  END b[1]
  PIN b[200]
    DIRECTION OUTPUT ;
    USE SIGNAL ;
    PORT
      LAYER M4 ;
        RECT  0 38.736 0.084 38.76 ;
    END
  END b[200]
  PIN b[201]
    DIRECTION OUTPUT ;
    USE SIGNAL ;
    PORT
      LAYER M4 ;
        RECT  0 38.832 0.084 38.856 ;
    END
  END b[201]
  PIN b[202]
    DIRECTION OUTPUT ;
    USE SIGNAL ;
    PORT
      LAYER M4 ;
        RECT  0 38.928 0.084 38.952 ;
    END
  END b[202]
  PIN b[203]
    DIRECTION OUTPUT ;
    USE SIGNAL ;
    PORT
      LAYER M4 ;
        RECT  0 39.024 0.084 39.048 ;
    END
  END b[203]
  PIN b[204]
    DIRECTION OUTPUT ;
    USE SIGNAL ;
    PORT
      LAYER M4 ;
        RECT  0 39.12 0.084 39.144 ;
    END
  END b[204]
  PIN b[205]
    DIRECTION OUTPUT ;
    USE SIGNAL ;
    PORT
      LAYER M4 ;
        RECT  0 39.216 0.084 39.24 ;
    END
  END b[205]
  PIN b[206]
    DIRECTION OUTPUT ;
    USE SIGNAL ;
    PORT
      LAYER M4 ;
        RECT  0 39.312 0.084 39.336 ;
    END
  END b[206]
  PIN b[207]
    DIRECTION OUTPUT ;
    USE SIGNAL ;
    PORT
      LAYER M4 ;
        RECT  0 39.408 0.084 39.432 ;
    END
  END b[207]
  PIN b[208]
    DIRECTION OUTPUT ;
    USE SIGNAL ;
    PORT
      LAYER M4 ;
        RECT  0 39.504 0.084 39.528 ;
    END
  END b[208]
  PIN b[209]
    DIRECTION OUTPUT ;
    USE SIGNAL ;
    PORT
      LAYER M4 ;
        RECT  0 39.6 0.084 39.624 ;
    END
  END b[209]
  PIN b[20]
    DIRECTION OUTPUT ;
    USE SIGNAL ;
    PORT
      LAYER M4 ;
        RECT  0 23.76 0.084 23.784 ;
    END
  END b[20]
  PIN b[210]
    DIRECTION OUTPUT ;
    USE SIGNAL ;
    PORT
      LAYER M4 ;
        RECT  0 39.696 0.084 39.72 ;
    END
  END b[210]
  PIN b[211]
    DIRECTION OUTPUT ;
    USE SIGNAL ;
    PORT
      LAYER M4 ;
        RECT  0 39.792 0.084 39.816 ;
    END
  END b[211]
  PIN b[212]
    DIRECTION OUTPUT ;
    USE SIGNAL ;
    PORT
      LAYER M4 ;
        RECT  0 39.888 0.084 39.912 ;
    END
  END b[212]
  PIN b[213]
    DIRECTION OUTPUT ;
    USE SIGNAL ;
    PORT
      LAYER M4 ;
        RECT  0 39.984 0.084 40.008 ;
    END
  END b[213]
  PIN b[214]
    DIRECTION OUTPUT ;
    USE SIGNAL ;
    PORT
      LAYER M4 ;
        RECT  0 40.08 0.084 40.104 ;
    END
  END b[214]
  PIN b[215]
    DIRECTION OUTPUT ;
    USE SIGNAL ;
    PORT
      LAYER M4 ;
        RECT  0 40.176 0.084 40.2 ;
    END
  END b[215]
  PIN b[216]
    DIRECTION OUTPUT ;
    USE SIGNAL ;
    PORT
      LAYER M4 ;
        RECT  0 40.272 0.084 40.296 ;
    END
  END b[216]
  PIN b[217]
    DIRECTION OUTPUT ;
    USE SIGNAL ;
    PORT
      LAYER M4 ;
        RECT  0 40.368 0.084 40.392 ;
    END
  END b[217]
  PIN b[218]
    DIRECTION OUTPUT ;
    USE SIGNAL ;
    PORT
      LAYER M4 ;
        RECT  0 40.464 0.084 40.488 ;
    END
  END b[218]
  PIN b[219]
    DIRECTION OUTPUT ;
    USE SIGNAL ;
    PORT
      LAYER M4 ;
        RECT  0 40.56 0.084 40.584 ;
    END
  END b[219]
  PIN b[21]
    DIRECTION OUTPUT ;
    USE SIGNAL ;
    PORT
      LAYER M4 ;
        RECT  0 23.856 0.084 23.88 ;
    END
  END b[21]
  PIN b[220]
    DIRECTION OUTPUT ;
    USE SIGNAL ;
    PORT
      LAYER M4 ;
        RECT  0 40.656 0.084 40.68 ;
    END
  END b[220]
  PIN b[221]
    DIRECTION OUTPUT ;
    USE SIGNAL ;
    PORT
      LAYER M4 ;
        RECT  0 40.752 0.084 40.776 ;
    END
  END b[221]
  PIN b[222]
    DIRECTION OUTPUT ;
    USE SIGNAL ;
    PORT
      LAYER M4 ;
        RECT  0 40.848 0.084 40.872 ;
    END
  END b[222]
  PIN b[223]
    DIRECTION OUTPUT ;
    USE SIGNAL ;
    PORT
      LAYER M4 ;
        RECT  0 40.944 0.084 40.968 ;
    END
  END b[223]
  PIN b[224]
    DIRECTION OUTPUT ;
    USE SIGNAL ;
    PORT
      LAYER M4 ;
        RECT  0 34.896 0.084 34.92 ;
    END
  END b[224]
  PIN b[225]
    DIRECTION OUTPUT ;
    USE SIGNAL ;
    PORT
      LAYER M4 ;
        RECT  0 34.992 0.084 35.016 ;
    END
  END b[225]
  PIN b[226]
    DIRECTION OUTPUT ;
    USE SIGNAL ;
    PORT
      LAYER M4 ;
        RECT  0 35.088 0.084 35.112 ;
    END
  END b[226]
  PIN b[227]
    DIRECTION OUTPUT ;
    USE SIGNAL ;
    PORT
      LAYER M4 ;
        RECT  0 35.184 0.084 35.208 ;
    END
  END b[227]
  PIN b[228]
    DIRECTION OUTPUT ;
    USE SIGNAL ;
    PORT
      LAYER M4 ;
        RECT  0 35.28 0.084 35.304 ;
    END
  END b[228]
  PIN b[229]
    DIRECTION OUTPUT ;
    USE SIGNAL ;
    PORT
      LAYER M4 ;
        RECT  0 35.376 0.084 35.4 ;
    END
  END b[229]
  PIN b[22]
    DIRECTION OUTPUT ;
    USE SIGNAL ;
    PORT
      LAYER M4 ;
        RECT  0 23.952 0.084 23.976 ;
    END
  END b[22]
  PIN b[230]
    DIRECTION OUTPUT ;
    USE SIGNAL ;
    PORT
      LAYER M4 ;
        RECT  0 35.472 0.084 35.496 ;
    END
  END b[230]
  PIN b[231]
    DIRECTION OUTPUT ;
    USE SIGNAL ;
    PORT
      LAYER M4 ;
        RECT  0 35.568 0.084 35.592 ;
    END
  END b[231]
  PIN b[232]
    DIRECTION OUTPUT ;
    USE SIGNAL ;
    PORT
      LAYER M4 ;
        RECT  0 35.664 0.084 35.688 ;
    END
  END b[232]
  PIN b[233]
    DIRECTION OUTPUT ;
    USE SIGNAL ;
    PORT
      LAYER M4 ;
        RECT  0 35.76 0.084 35.784 ;
    END
  END b[233]
  PIN b[234]
    DIRECTION OUTPUT ;
    USE SIGNAL ;
    PORT
      LAYER M4 ;
        RECT  0 35.856 0.084 35.88 ;
    END
  END b[234]
  PIN b[235]
    DIRECTION OUTPUT ;
    USE SIGNAL ;
    PORT
      LAYER M4 ;
        RECT  0 35.952 0.084 35.976 ;
    END
  END b[235]
  PIN b[236]
    DIRECTION OUTPUT ;
    USE SIGNAL ;
    PORT
      LAYER M4 ;
        RECT  0 36.048 0.084 36.072 ;
    END
  END b[236]
  PIN b[237]
    DIRECTION OUTPUT ;
    USE SIGNAL ;
    PORT
      LAYER M4 ;
        RECT  0 36.144 0.084 36.168 ;
    END
  END b[237]
  PIN b[238]
    DIRECTION OUTPUT ;
    USE SIGNAL ;
    PORT
      LAYER M4 ;
        RECT  0 36.24 0.084 36.264 ;
    END
  END b[238]
  PIN b[239]
    DIRECTION OUTPUT ;
    USE SIGNAL ;
    PORT
      LAYER M4 ;
        RECT  0 36.336 0.084 36.36 ;
    END
  END b[239]
  PIN b[23]
    DIRECTION OUTPUT ;
    USE SIGNAL ;
    PORT
      LAYER M4 ;
        RECT  0 24.048 0.084 24.072 ;
    END
  END b[23]
  PIN b[240]
    DIRECTION OUTPUT ;
    USE SIGNAL ;
    PORT
      LAYER M4 ;
        RECT  0 36.432 0.084 36.456 ;
    END
  END b[240]
  PIN b[241]
    DIRECTION OUTPUT ;
    USE SIGNAL ;
    PORT
      LAYER M4 ;
        RECT  0 36.528 0.084 36.552 ;
    END
  END b[241]
  PIN b[242]
    DIRECTION OUTPUT ;
    USE SIGNAL ;
    PORT
      LAYER M4 ;
        RECT  0 36.624 0.084 36.648 ;
    END
  END b[242]
  PIN b[243]
    DIRECTION OUTPUT ;
    USE SIGNAL ;
    PORT
      LAYER M4 ;
        RECT  0 36.72 0.084 36.744 ;
    END
  END b[243]
  PIN b[244]
    DIRECTION OUTPUT ;
    USE SIGNAL ;
    PORT
      LAYER M4 ;
        RECT  0 36.816 0.084 36.84 ;
    END
  END b[244]
  PIN b[245]
    DIRECTION OUTPUT ;
    USE SIGNAL ;
    PORT
      LAYER M4 ;
        RECT  0 36.912 0.084 36.936 ;
    END
  END b[245]
  PIN b[246]
    DIRECTION OUTPUT ;
    USE SIGNAL ;
    PORT
      LAYER M4 ;
        RECT  0 37.008 0.084 37.032 ;
    END
  END b[246]
  PIN b[247]
    DIRECTION OUTPUT ;
    USE SIGNAL ;
    PORT
      LAYER M4 ;
        RECT  0 37.104 0.084 37.128 ;
    END
  END b[247]
  PIN b[248]
    DIRECTION OUTPUT ;
    USE SIGNAL ;
    PORT
      LAYER M4 ;
        RECT  0 37.2 0.084 37.224 ;
    END
  END b[248]
  PIN b[249]
    DIRECTION OUTPUT ;
    USE SIGNAL ;
    PORT
      LAYER M4 ;
        RECT  0 37.296 0.084 37.32 ;
    END
  END b[249]
  PIN b[24]
    DIRECTION OUTPUT ;
    USE SIGNAL ;
    PORT
      LAYER M4 ;
        RECT  0 24.144 0.084 24.168 ;
    END
  END b[24]
  PIN b[250]
    DIRECTION OUTPUT ;
    USE SIGNAL ;
    PORT
      LAYER M4 ;
        RECT  0 37.392 0.084 37.416 ;
    END
  END b[250]
  PIN b[251]
    DIRECTION OUTPUT ;
    USE SIGNAL ;
    PORT
      LAYER M4 ;
        RECT  0 37.488 0.084 37.512 ;
    END
  END b[251]
  PIN b[252]
    DIRECTION OUTPUT ;
    USE SIGNAL ;
    PORT
      LAYER M4 ;
        RECT  0 37.584 0.084 37.608 ;
    END
  END b[252]
  PIN b[253]
    DIRECTION OUTPUT ;
    USE SIGNAL ;
    PORT
      LAYER M4 ;
        RECT  0 37.68 0.084 37.704 ;
    END
  END b[253]
  PIN b[254]
    DIRECTION OUTPUT ;
    USE SIGNAL ;
    PORT
      LAYER M4 ;
        RECT  0 37.776 0.084 37.8 ;
    END
  END b[254]
  PIN b[255]
    DIRECTION OUTPUT ;
    USE SIGNAL ;
    PORT
      LAYER M4 ;
        RECT  0 37.872 0.084 37.896 ;
    END
  END b[255]
  PIN b[256]
    DIRECTION OUTPUT ;
    USE SIGNAL ;
    PORT
      LAYER M4 ;
        RECT  0 42.192 0.084 42.216 ;
    END
  END b[256]
  PIN b[257]
    DIRECTION OUTPUT ;
    USE SIGNAL ;
    PORT
      LAYER M4 ;
        RECT  0 42.288 0.084 42.312 ;
    END
  END b[257]
  PIN b[258]
    DIRECTION OUTPUT ;
    USE SIGNAL ;
    PORT
      LAYER M4 ;
        RECT  0 42.384 0.084 42.408 ;
    END
  END b[258]
  PIN b[259]
    DIRECTION OUTPUT ;
    USE SIGNAL ;
    PORT
      LAYER M4 ;
        RECT  0 42.48 0.084 42.504 ;
    END
  END b[259]
  PIN b[25]
    DIRECTION OUTPUT ;
    USE SIGNAL ;
    PORT
      LAYER M4 ;
        RECT  0 24.24 0.084 24.264 ;
    END
  END b[25]
  PIN b[260]
    DIRECTION OUTPUT ;
    USE SIGNAL ;
    PORT
      LAYER M4 ;
        RECT  0 42.576 0.084 42.6 ;
    END
  END b[260]
  PIN b[261]
    DIRECTION OUTPUT ;
    USE SIGNAL ;
    PORT
      LAYER M4 ;
        RECT  0 42.672 0.084 42.696 ;
    END
  END b[261]
  PIN b[262]
    DIRECTION OUTPUT ;
    USE SIGNAL ;
    PORT
      LAYER M4 ;
        RECT  0 42.768 0.084 42.792 ;
    END
  END b[262]
  PIN b[263]
    DIRECTION OUTPUT ;
    USE SIGNAL ;
    PORT
      LAYER M4 ;
        RECT  0 42.864 0.084 42.888 ;
    END
  END b[263]
  PIN b[264]
    DIRECTION OUTPUT ;
    USE SIGNAL ;
    PORT
      LAYER M4 ;
        RECT  0 42.96 0.084 42.984 ;
    END
  END b[264]
  PIN b[265]
    DIRECTION OUTPUT ;
    USE SIGNAL ;
    PORT
      LAYER M4 ;
        RECT  0 43.056 0.084 43.08 ;
    END
  END b[265]
  PIN b[266]
    DIRECTION OUTPUT ;
    USE SIGNAL ;
    PORT
      LAYER M4 ;
        RECT  0 43.152 0.084 43.176 ;
    END
  END b[266]
  PIN b[267]
    DIRECTION OUTPUT ;
    USE SIGNAL ;
    PORT
      LAYER M4 ;
        RECT  0 43.248 0.084 43.272 ;
    END
  END b[267]
  PIN b[268]
    DIRECTION OUTPUT ;
    USE SIGNAL ;
    PORT
      LAYER M4 ;
        RECT  0 43.344 0.084 43.368 ;
    END
  END b[268]
  PIN b[269]
    DIRECTION OUTPUT ;
    USE SIGNAL ;
    PORT
      LAYER M4 ;
        RECT  0 43.44 0.084 43.464 ;
    END
  END b[269]
  PIN b[26]
    DIRECTION OUTPUT ;
    USE SIGNAL ;
    PORT
      LAYER M4 ;
        RECT  0 24.336 0.084 24.36 ;
    END
  END b[26]
  PIN b[270]
    DIRECTION OUTPUT ;
    USE SIGNAL ;
    PORT
      LAYER M4 ;
        RECT  0 43.536 0.084 43.56 ;
    END
  END b[270]
  PIN b[271]
    DIRECTION OUTPUT ;
    USE SIGNAL ;
    PORT
      LAYER M4 ;
        RECT  0 43.632 0.084 43.656 ;
    END
  END b[271]
  PIN b[27]
    DIRECTION OUTPUT ;
    USE SIGNAL ;
    PORT
      LAYER M4 ;
        RECT  0 24.432 0.084 24.456 ;
    END
  END b[27]
  PIN b[28]
    DIRECTION OUTPUT ;
    USE SIGNAL ;
    PORT
      LAYER M4 ;
        RECT  0 24.528 0.084 24.552 ;
    END
  END b[28]
  PIN b[29]
    DIRECTION OUTPUT ;
    USE SIGNAL ;
    PORT
      LAYER M4 ;
        RECT  0 24.624 0.084 24.648 ;
    END
  END b[29]
  PIN b[2]
    DIRECTION OUTPUT ;
    USE SIGNAL ;
    PORT
      LAYER M4 ;
        RECT  0 22.032 0.084 22.056 ;
    END
  END b[2]
  PIN b[30]
    DIRECTION OUTPUT ;
    USE SIGNAL ;
    PORT
      LAYER M4 ;
        RECT  0 24.72 0.084 24.744 ;
    END
  END b[30]
  PIN b[31]
    DIRECTION OUTPUT ;
    USE SIGNAL ;
    PORT
      LAYER M4 ;
        RECT  0 24.816 0.084 24.84 ;
    END
  END b[31]
  PIN b[32]
    DIRECTION OUTPUT ;
    USE SIGNAL ;
    PORT
      LAYER M4 ;
        RECT  0 27.984 0.084 28.008 ;
    END
  END b[32]
  PIN b[33]
    DIRECTION OUTPUT ;
    USE SIGNAL ;
    PORT
      LAYER M4 ;
        RECT  0 28.08 0.084 28.104 ;
    END
  END b[33]
  PIN b[34]
    DIRECTION OUTPUT ;
    USE SIGNAL ;
    PORT
      LAYER M4 ;
        RECT  0 28.176 0.084 28.2 ;
    END
  END b[34]
  PIN b[35]
    DIRECTION OUTPUT ;
    USE SIGNAL ;
    PORT
      LAYER M4 ;
        RECT  0 28.272 0.084 28.296 ;
    END
  END b[35]
  PIN b[36]
    DIRECTION OUTPUT ;
    USE SIGNAL ;
    PORT
      LAYER M4 ;
        RECT  0 28.368 0.084 28.392 ;
    END
  END b[36]
  PIN b[37]
    DIRECTION OUTPUT ;
    USE SIGNAL ;
    PORT
      LAYER M4 ;
        RECT  0 28.464 0.084 28.488 ;
    END
  END b[37]
  PIN b[38]
    DIRECTION OUTPUT ;
    USE SIGNAL ;
    PORT
      LAYER M4 ;
        RECT  0 28.56 0.084 28.584 ;
    END
  END b[38]
  PIN b[39]
    DIRECTION OUTPUT ;
    USE SIGNAL ;
    PORT
      LAYER M4 ;
        RECT  0 28.656 0.084 28.68 ;
    END
  END b[39]
  PIN b[3]
    DIRECTION OUTPUT ;
    USE SIGNAL ;
    PORT
      LAYER M4 ;
        RECT  0 22.128 0.084 22.152 ;
    END
  END b[3]
  PIN b[40]
    DIRECTION OUTPUT ;
    USE SIGNAL ;
    PORT
      LAYER M4 ;
        RECT  0 28.752 0.084 28.776 ;
    END
  END b[40]
  PIN b[41]
    DIRECTION OUTPUT ;
    USE SIGNAL ;
    PORT
      LAYER M4 ;
        RECT  0 28.848 0.084 28.872 ;
    END
  END b[41]
  PIN b[42]
    DIRECTION OUTPUT ;
    USE SIGNAL ;
    PORT
      LAYER M4 ;
        RECT  0 28.944 0.084 28.968 ;
    END
  END b[42]
  PIN b[43]
    DIRECTION OUTPUT ;
    USE SIGNAL ;
    PORT
      LAYER M4 ;
        RECT  0 29.04 0.084 29.064 ;
    END
  END b[43]
  PIN b[44]
    DIRECTION OUTPUT ;
    USE SIGNAL ;
    PORT
      LAYER M4 ;
        RECT  0 29.136 0.084 29.16 ;
    END
  END b[44]
  PIN b[45]
    DIRECTION OUTPUT ;
    USE SIGNAL ;
    PORT
      LAYER M4 ;
        RECT  0 29.232 0.084 29.256 ;
    END
  END b[45]
  PIN b[46]
    DIRECTION OUTPUT ;
    USE SIGNAL ;
    PORT
      LAYER M4 ;
        RECT  0 29.328 0.084 29.352 ;
    END
  END b[46]
  PIN b[47]
    DIRECTION OUTPUT ;
    USE SIGNAL ;
    PORT
      LAYER M4 ;
        RECT  0 29.424 0.084 29.448 ;
    END
  END b[47]
  PIN b[48]
    DIRECTION OUTPUT ;
    USE SIGNAL ;
    PORT
      LAYER M4 ;
        RECT  0 29.52 0.084 29.544 ;
    END
  END b[48]
  PIN b[49]
    DIRECTION OUTPUT ;
    USE SIGNAL ;
    PORT
      LAYER M4 ;
        RECT  0 29.616 0.084 29.64 ;
    END
  END b[49]
  PIN b[4]
    DIRECTION OUTPUT ;
    USE SIGNAL ;
    PORT
      LAYER M4 ;
        RECT  0 22.224 0.084 22.248 ;
    END
  END b[4]
  PIN b[50]
    DIRECTION OUTPUT ;
    USE SIGNAL ;
    PORT
      LAYER M4 ;
        RECT  0 29.712 0.084 29.736 ;
    END
  END b[50]
  PIN b[51]
    DIRECTION OUTPUT ;
    USE SIGNAL ;
    PORT
      LAYER M4 ;
        RECT  0 29.808 0.084 29.832 ;
    END
  END b[51]
  PIN b[52]
    DIRECTION OUTPUT ;
    USE SIGNAL ;
    PORT
      LAYER M4 ;
        RECT  0 29.904 0.084 29.928 ;
    END
  END b[52]
  PIN b[53]
    DIRECTION OUTPUT ;
    USE SIGNAL ;
    PORT
      LAYER M4 ;
        RECT  0 30 0.084 30.024 ;
    END
  END b[53]
  PIN b[54]
    DIRECTION OUTPUT ;
    USE SIGNAL ;
    PORT
      LAYER M4 ;
        RECT  0 30.096 0.084 30.12 ;
    END
  END b[54]
  PIN b[55]
    DIRECTION OUTPUT ;
    USE SIGNAL ;
    PORT
      LAYER M4 ;
        RECT  0 30.192 0.084 30.216 ;
    END
  END b[55]
  PIN b[56]
    DIRECTION OUTPUT ;
    USE SIGNAL ;
    PORT
      LAYER M4 ;
        RECT  0 30.288 0.084 30.312 ;
    END
  END b[56]
  PIN b[57]
    DIRECTION OUTPUT ;
    USE SIGNAL ;
    PORT
      LAYER M4 ;
        RECT  0 30.384 0.084 30.408 ;
    END
  END b[57]
  PIN b[58]
    DIRECTION OUTPUT ;
    USE SIGNAL ;
    PORT
      LAYER M4 ;
        RECT  0 30.48 0.084 30.504 ;
    END
  END b[58]
  PIN b[59]
    DIRECTION OUTPUT ;
    USE SIGNAL ;
    PORT
      LAYER M4 ;
        RECT  0 30.576 0.084 30.6 ;
    END
  END b[59]
  PIN b[5]
    DIRECTION OUTPUT ;
    USE SIGNAL ;
    PORT
      LAYER M4 ;
        RECT  0 22.32 0.084 22.344 ;
    END
  END b[5]
  PIN b[60]
    DIRECTION OUTPUT ;
    USE SIGNAL ;
    PORT
      LAYER M4 ;
        RECT  0 30.672 0.084 30.696 ;
    END
  END b[60]
  PIN b[61]
    DIRECTION OUTPUT ;
    USE SIGNAL ;
    PORT
      LAYER M4 ;
        RECT  0 30.768 0.084 30.792 ;
    END
  END b[61]
  PIN b[62]
    DIRECTION OUTPUT ;
    USE SIGNAL ;
    PORT
      LAYER M4 ;
        RECT  0 30.864 0.084 30.888 ;
    END
  END b[62]
  PIN b[63]
    DIRECTION OUTPUT ;
    USE SIGNAL ;
    PORT
      LAYER M4 ;
        RECT  0 30.96 0.084 30.984 ;
    END
  END b[63]
  PIN b[64]
    DIRECTION OUTPUT ;
    USE SIGNAL ;
    PORT
      LAYER M4 ;
        RECT  0 24.912 0.084 24.936 ;
    END
  END b[64]
  PIN b[65]
    DIRECTION OUTPUT ;
    USE SIGNAL ;
    PORT
      LAYER M4 ;
        RECT  0 25.008 0.084 25.032 ;
    END
  END b[65]
  PIN b[66]
    DIRECTION OUTPUT ;
    USE SIGNAL ;
    PORT
      LAYER M4 ;
        RECT  0 25.104 0.084 25.128 ;
    END
  END b[66]
  PIN b[67]
    DIRECTION OUTPUT ;
    USE SIGNAL ;
    PORT
      LAYER M4 ;
        RECT  0 25.2 0.084 25.224 ;
    END
  END b[67]
  PIN b[68]
    DIRECTION OUTPUT ;
    USE SIGNAL ;
    PORT
      LAYER M4 ;
        RECT  0 25.296 0.084 25.32 ;
    END
  END b[68]
  PIN b[69]
    DIRECTION OUTPUT ;
    USE SIGNAL ;
    PORT
      LAYER M4 ;
        RECT  0 25.392 0.084 25.416 ;
    END
  END b[69]
  PIN b[6]
    DIRECTION OUTPUT ;
    USE SIGNAL ;
    PORT
      LAYER M4 ;
        RECT  0 22.416 0.084 22.44 ;
    END
  END b[6]
  PIN b[70]
    DIRECTION OUTPUT ;
    USE SIGNAL ;
    PORT
      LAYER M4 ;
        RECT  0 25.488 0.084 25.512 ;
    END
  END b[70]
  PIN b[71]
    DIRECTION OUTPUT ;
    USE SIGNAL ;
    PORT
      LAYER M4 ;
        RECT  0 25.584 0.084 25.608 ;
    END
  END b[71]
  PIN b[72]
    DIRECTION OUTPUT ;
    USE SIGNAL ;
    PORT
      LAYER M4 ;
        RECT  0 25.68 0.084 25.704 ;
    END
  END b[72]
  PIN b[73]
    DIRECTION OUTPUT ;
    USE SIGNAL ;
    PORT
      LAYER M4 ;
        RECT  0 25.776 0.084 25.8 ;
    END
  END b[73]
  PIN b[74]
    DIRECTION OUTPUT ;
    USE SIGNAL ;
    PORT
      LAYER M4 ;
        RECT  0 25.872 0.084 25.896 ;
    END
  END b[74]
  PIN b[75]
    DIRECTION OUTPUT ;
    USE SIGNAL ;
    PORT
      LAYER M4 ;
        RECT  0 25.968 0.084 25.992 ;
    END
  END b[75]
  PIN b[76]
    DIRECTION OUTPUT ;
    USE SIGNAL ;
    PORT
      LAYER M4 ;
        RECT  0 26.064 0.084 26.088 ;
    END
  END b[76]
  PIN b[77]
    DIRECTION OUTPUT ;
    USE SIGNAL ;
    PORT
      LAYER M4 ;
        RECT  0 26.16 0.084 26.184 ;
    END
  END b[77]
  PIN b[78]
    DIRECTION OUTPUT ;
    USE SIGNAL ;
    PORT
      LAYER M4 ;
        RECT  0 26.256 0.084 26.28 ;
    END
  END b[78]
  PIN b[79]
    DIRECTION OUTPUT ;
    USE SIGNAL ;
    PORT
      LAYER M4 ;
        RECT  0 26.352 0.084 26.376 ;
    END
  END b[79]
  PIN b[7]
    DIRECTION OUTPUT ;
    USE SIGNAL ;
    PORT
      LAYER M4 ;
        RECT  0 22.512 0.084 22.536 ;
    END
  END b[7]
  PIN b[80]
    DIRECTION OUTPUT ;
    USE SIGNAL ;
    PORT
      LAYER M4 ;
        RECT  0 26.448 0.084 26.472 ;
    END
  END b[80]
  PIN b[81]
    DIRECTION OUTPUT ;
    USE SIGNAL ;
    PORT
      LAYER M4 ;
        RECT  0 26.544 0.084 26.568 ;
    END
  END b[81]
  PIN b[82]
    DIRECTION OUTPUT ;
    USE SIGNAL ;
    PORT
      LAYER M4 ;
        RECT  0 26.64 0.084 26.664 ;
    END
  END b[82]
  PIN b[83]
    DIRECTION OUTPUT ;
    USE SIGNAL ;
    PORT
      LAYER M4 ;
        RECT  0 26.736 0.084 26.76 ;
    END
  END b[83]
  PIN b[84]
    DIRECTION OUTPUT ;
    USE SIGNAL ;
    PORT
      LAYER M4 ;
        RECT  0 26.832 0.084 26.856 ;
    END
  END b[84]
  PIN b[85]
    DIRECTION OUTPUT ;
    USE SIGNAL ;
    PORT
      LAYER M4 ;
        RECT  0 26.928 0.084 26.952 ;
    END
  END b[85]
  PIN b[86]
    DIRECTION OUTPUT ;
    USE SIGNAL ;
    PORT
      LAYER M4 ;
        RECT  0 27.024 0.084 27.048 ;
    END
  END b[86]
  PIN b[87]
    DIRECTION OUTPUT ;
    USE SIGNAL ;
    PORT
      LAYER M4 ;
        RECT  0 27.12 0.084 27.144 ;
    END
  END b[87]
  PIN b[88]
    DIRECTION OUTPUT ;
    USE SIGNAL ;
    PORT
      LAYER M4 ;
        RECT  0 27.216 0.084 27.24 ;
    END
  END b[88]
  PIN b[89]
    DIRECTION OUTPUT ;
    USE SIGNAL ;
    PORT
      LAYER M4 ;
        RECT  0 27.312 0.084 27.336 ;
    END
  END b[89]
  PIN b[8]
    DIRECTION OUTPUT ;
    USE SIGNAL ;
    PORT
      LAYER M4 ;
        RECT  0 22.608 0.084 22.632 ;
    END
  END b[8]
  PIN b[90]
    DIRECTION OUTPUT ;
    USE SIGNAL ;
    PORT
      LAYER M4 ;
        RECT  0 27.408 0.084 27.432 ;
    END
  END b[90]
  PIN b[91]
    DIRECTION OUTPUT ;
    USE SIGNAL ;
    PORT
      LAYER M4 ;
        RECT  0 27.504 0.084 27.528 ;
    END
  END b[91]
  PIN b[92]
    DIRECTION OUTPUT ;
    USE SIGNAL ;
    PORT
      LAYER M4 ;
        RECT  0 27.6 0.084 27.624 ;
    END
  END b[92]
  PIN b[93]
    DIRECTION OUTPUT ;
    USE SIGNAL ;
    PORT
      LAYER M4 ;
        RECT  0 27.696 0.084 27.72 ;
    END
  END b[93]
  PIN b[94]
    DIRECTION OUTPUT ;
    USE SIGNAL ;
    PORT
      LAYER M4 ;
        RECT  0 27.792 0.084 27.816 ;
    END
  END b[94]
  PIN b[95]
    DIRECTION OUTPUT ;
    USE SIGNAL ;
    PORT
      LAYER M4 ;
        RECT  0 27.888 0.084 27.912 ;
    END
  END b[95]
  PIN b[96]
    DIRECTION OUTPUT ;
    USE SIGNAL ;
    PORT
      LAYER M4 ;
        RECT  0 15.696 0.084 15.72 ;
    END
  END b[96]
  PIN b[97]
    DIRECTION OUTPUT ;
    USE SIGNAL ;
    PORT
      LAYER M4 ;
        RECT  0 15.792 0.084 15.816 ;
    END
  END b[97]
  PIN b[98]
    DIRECTION OUTPUT ;
    USE SIGNAL ;
    PORT
      LAYER M4 ;
        RECT  0 15.888 0.084 15.912 ;
    END
  END b[98]
  PIN b[99]
    DIRECTION OUTPUT ;
    USE SIGNAL ;
    PORT
      LAYER M4 ;
        RECT  0 15.984 0.084 16.008 ;
    END
  END b[99]
  PIN b[9]
    DIRECTION OUTPUT ;
    USE SIGNAL ;
    PORT
      LAYER M4 ;
        RECT  0 22.704 0.084 22.728 ;
    END
  END b[9]
  PIN ck_o[0]
    DIRECTION OUTPUT ;
    USE SIGNAL ;
    PORT
      LAYER M4 ;
        RECT  0 43.728 0.084 43.752 ;
    END
  END ck_o[0]
  PIN ck_o[1]
    DIRECTION OUTPUT ;
    USE SIGNAL ;
    PORT
      LAYER M4 ;
        RECT  0 43.824 0.084 43.848 ;
    END
  END ck_o[1]
  PIN ckf
    DIRECTION INPUT ;
    USE SIGNAL ;
    PORT
      LAYER M4 ;
        RECT  21.516 20.688 21.6 20.712 ;
    END
  END ckf
  PIN ea
    DIRECTION INPUT ;
    USE SIGNAL ;
    PORT
      LAYER M4 ;
        RECT  21.516 20.784 21.6 20.808 ;
    END
  END ea
  PIN eb[0]
    DIRECTION OUTPUT ;
    USE SIGNAL ;
    PORT
      LAYER M4 ;
        RECT  0 43.92 0.084 43.944 ;
    END
  END eb[0]
  PIN eb[1]
    DIRECTION OUTPUT ;
    USE SIGNAL ;
    PORT
      LAYER M4 ;
        RECT  0 44.016 0.084 44.04 ;
    END
  END eb[1]
  PIN VDD
    DIRECTION INOUT ;
    USE POWER ;
    PORT
      LAYER M5 ;
        RECT  18.792 2.151 18.912 51.849 ;
        RECT  16.092 2.151 16.212 51.849 ;
        RECT  13.392 2.151 13.512 51.849 ;
        RECT  10.692 2.151 10.812 51.849 ;
        RECT  7.992 2.151 8.112 51.849 ;
        RECT  5.292 2.151 5.412 51.849 ;
        RECT  2.592 2.151 2.712 51.849 ;
    END
  END VDD
  PIN VSS
    DIRECTION INOUT ;
    USE GROUND ;
    PORT
      LAYER M5 ;
        RECT  18.6 2.137 18.72 51.863 ;
        RECT  15.9 2.137 16.02 51.863 ;
        RECT  13.2 2.137 13.32 51.863 ;
        RECT  10.5 2.137 10.62 51.863 ;
        RECT  7.8 2.137 7.92 51.863 ;
        RECT  5.1 2.137 5.22 51.863 ;
        RECT  2.4 2.137 2.52 51.863 ;
    END
  END VSS
  # OT_OBS_CLOSED layer=M5 d_um=1.536 added=12
  OBS
    LAYER RVTN ;
     RECT  2.16 2.16 19.44 2.295 ;
     RECT  2.16 2.565 19.44 2.835 ;
     RECT  2.16 3.105 19.44 3.375 ;
     RECT  2.16 3.645 19.44 3.915 ;
     RECT  2.16 4.185 19.44 4.455 ;
     RECT  2.16 4.725 19.44 4.995 ;
     RECT  2.16 5.265 19.44 5.535 ;
     RECT  2.16 5.805 19.44 6.075 ;
     RECT  2.16 6.345 19.44 6.615 ;
     RECT  2.16 6.885 19.44 7.155 ;
     RECT  2.16 7.425 19.44 7.695 ;
     RECT  2.16 7.965 19.44 8.235 ;
     RECT  2.16 8.505 19.44 8.775 ;
     RECT  2.16 9.045 19.44 9.315 ;
     RECT  2.16 9.585 19.44 9.855 ;
     RECT  2.16 10.125 19.44 10.395 ;
     RECT  2.16 10.665 19.44 10.935 ;
     RECT  2.16 11.205 19.44 11.475 ;
     RECT  2.16 11.745 19.44 12.015 ;
     RECT  2.16 12.285 19.44 12.555 ;
     RECT  2.16 12.825 19.44 13.095 ;
     RECT  2.16 13.365 19.44 13.635 ;
     RECT  2.16 13.905 19.44 14.175 ;
     RECT  2.16 14.445 19.44 14.715 ;
     RECT  2.16 14.985 19.44 15.255 ;
     RECT  2.16 15.525 19.44 15.795 ;
     RECT  2.16 16.065 19.44 16.335 ;
     RECT  2.16 16.605 19.44 16.875 ;
     RECT  2.16 17.145 19.44 17.415 ;
     RECT  2.16 17.685 19.44 17.955 ;
     RECT  2.16 18.225 19.44 18.495 ;
     RECT  2.16 18.765 19.44 19.035 ;
     RECT  2.16 19.305 19.44 19.575 ;
     RECT  2.16 19.845 19.44 20.115 ;
     RECT  2.16 20.385 19.44 20.655 ;
     RECT  2.16 20.925 19.44 21.195 ;
     RECT  2.16 21.465 19.44 21.735 ;
     RECT  2.16 22.005 19.44 22.275 ;
     RECT  2.16 22.545 19.44 22.815 ;
     RECT  2.16 23.085 19.44 23.355 ;
     RECT  2.16 23.625 19.44 23.895 ;
     RECT  2.16 24.165 19.44 24.435 ;
     RECT  2.16 24.705 19.44 24.975 ;
     RECT  2.16 25.245 19.44 25.515 ;
     RECT  2.16 25.785 19.44 26.055 ;
     RECT  2.16 26.325 19.44 26.595 ;
     RECT  2.16 26.865 19.44 27.135 ;
     RECT  2.16 27.405 19.44 27.675 ;
     RECT  2.16 27.945 19.44 28.215 ;
     RECT  2.16 28.485 19.44 28.755 ;
     RECT  2.16 29.025 19.44 29.295 ;
     RECT  2.16 29.565 19.44 29.835 ;
     RECT  2.16 30.105 19.44 30.375 ;
     RECT  2.16 30.645 19.44 30.915 ;
     RECT  2.16 31.185 19.44 31.455 ;
     RECT  2.16 31.725 19.44 31.995 ;
     RECT  2.16 32.265 19.44 32.535 ;
     RECT  2.16 32.805 19.44 33.075 ;
     RECT  2.16 33.345 19.44 33.615 ;
     RECT  2.16 33.885 19.44 34.155 ;
     RECT  2.16 34.425 19.44 34.695 ;
     RECT  2.16 34.965 19.44 35.235 ;
     RECT  2.16 35.505 19.44 35.775 ;
     RECT  2.16 36.045 19.44 36.315 ;
     RECT  2.16 36.585 19.44 36.855 ;
     RECT  2.16 37.125 19.44 37.395 ;
     RECT  2.16 37.665 19.44 37.935 ;
     RECT  2.16 38.205 19.44 38.475 ;
     RECT  2.16 38.745 19.44 39.015 ;
     RECT  2.16 39.285 19.44 39.555 ;
     RECT  2.16 39.825 19.44 40.095 ;
     RECT  2.16 40.365 19.44 40.635 ;
     RECT  2.16 40.905 19.44 41.175 ;
     RECT  2.16 41.445 19.44 41.715 ;
     RECT  2.16 41.985 19.44 42.255 ;
     RECT  2.16 42.525 19.44 42.795 ;
     RECT  2.16 43.065 19.44 43.335 ;
     RECT  2.16 43.605 19.44 43.875 ;
     RECT  2.16 44.145 19.44 44.415 ;
     RECT  2.16 44.685 19.44 44.955 ;
     RECT  2.16 45.225 19.44 45.495 ;
     RECT  2.16 45.765 19.44 46.035 ;
     RECT  2.16 46.305 19.44 46.575 ;
     RECT  2.16 46.845 19.44 47.115 ;
     RECT  2.16 47.385 19.44 47.655 ;
     RECT  2.16 47.925 19.44 48.195 ;
     RECT  2.16 48.465 19.44 48.735 ;
     RECT  2.16 49.005 19.44 49.275 ;
     RECT  2.16 49.545 19.44 49.815 ;
     RECT  2.16 50.085 19.44 50.355 ;
     RECT  2.16 50.625 19.44 50.895 ;
     RECT  2.16 51.165 19.44 51.435 ;
     RECT  2.16 51.705 19.44 51.84 ;
    LAYER RVTP ;
     RECT  2.16 2.295 19.44 2.565 ;
     RECT  2.16 2.835 19.44 3.105 ;
     RECT  2.16 3.375 19.44 3.645 ;
     RECT  2.16 3.915 19.44 4.185 ;
     RECT  2.16 4.455 19.44 4.725 ;
     RECT  2.16 4.995 19.44 5.265 ;
     RECT  2.16 5.535 19.44 5.805 ;
     RECT  2.16 6.075 19.44 6.345 ;
     RECT  2.16 6.615 19.44 6.885 ;
     RECT  2.16 7.155 19.44 7.425 ;
     RECT  2.16 7.695 19.44 7.965 ;
     RECT  2.16 8.235 19.44 8.505 ;
     RECT  2.16 8.775 19.44 9.045 ;
     RECT  2.16 9.315 19.44 9.585 ;
     RECT  2.16 9.855 19.44 10.125 ;
     RECT  2.16 10.395 19.44 10.665 ;
     RECT  2.16 10.935 19.44 11.205 ;
     RECT  2.16 11.475 19.44 11.745 ;
     RECT  2.16 12.015 19.44 12.285 ;
     RECT  2.16 12.555 19.44 12.825 ;
     RECT  2.16 13.095 19.44 13.365 ;
     RECT  2.16 13.635 19.44 13.905 ;
     RECT  2.16 14.175 19.44 14.445 ;
     RECT  2.16 14.715 19.44 14.985 ;
     RECT  2.16 15.255 19.44 15.525 ;
     RECT  2.16 15.795 19.44 16.065 ;
     RECT  2.16 16.335 19.44 16.605 ;
     RECT  2.16 16.875 19.44 17.145 ;
     RECT  2.16 17.415 19.44 17.685 ;
     RECT  2.16 17.955 19.44 18.225 ;
     RECT  2.16 18.495 19.44 18.765 ;
     RECT  2.16 19.035 19.44 19.305 ;
     RECT  2.16 19.575 19.44 19.845 ;
     RECT  2.16 20.115 19.44 20.385 ;
     RECT  2.16 20.655 19.44 20.925 ;
     RECT  2.16 21.195 19.44 21.465 ;
     RECT  2.16 21.735 19.44 22.005 ;
     RECT  2.16 22.275 19.44 22.545 ;
     RECT  2.16 22.815 19.44 23.085 ;
     RECT  2.16 23.355 19.44 23.625 ;
     RECT  2.16 23.895 19.44 24.165 ;
     RECT  2.16 24.435 19.44 24.705 ;
     RECT  2.16 24.975 19.44 25.245 ;
     RECT  2.16 25.515 19.44 25.785 ;
     RECT  2.16 26.055 19.44 26.325 ;
     RECT  2.16 26.595 19.44 26.865 ;
     RECT  2.16 27.135 19.44 27.405 ;
     RECT  2.16 27.675 19.44 27.945 ;
     RECT  2.16 28.215 19.44 28.485 ;
     RECT  2.16 28.755 19.44 29.025 ;
     RECT  2.16 29.295 19.44 29.565 ;
     RECT  2.16 29.835 19.44 30.105 ;
     RECT  2.16 30.375 19.44 30.645 ;
     RECT  2.16 30.915 19.44 31.185 ;
     RECT  2.16 31.455 19.44 31.725 ;
     RECT  2.16 31.995 19.44 32.265 ;
     RECT  2.16 32.535 19.44 32.805 ;
     RECT  2.16 33.075 19.44 33.345 ;
     RECT  2.16 33.615 19.44 33.885 ;
     RECT  2.16 34.155 19.44 34.425 ;
     RECT  2.16 34.695 19.44 34.965 ;
     RECT  2.16 35.235 19.44 35.505 ;
     RECT  2.16 35.775 19.44 36.045 ;
     RECT  2.16 36.315 19.44 36.585 ;
     RECT  2.16 36.855 19.44 37.125 ;
     RECT  2.16 37.395 19.44 37.665 ;
     RECT  2.16 37.935 19.44 38.205 ;
     RECT  2.16 38.475 19.44 38.745 ;
     RECT  2.16 39.015 19.44 39.285 ;
     RECT  2.16 39.555 19.44 39.825 ;
     RECT  2.16 40.095 19.44 40.365 ;
     RECT  2.16 40.635 19.44 40.905 ;
     RECT  2.16 41.175 19.44 41.445 ;
     RECT  2.16 41.715 19.44 41.985 ;
     RECT  2.16 42.255 19.44 42.525 ;
     RECT  2.16 42.795 19.44 43.065 ;
     RECT  2.16 43.335 19.44 43.605 ;
     RECT  2.16 43.875 19.44 44.145 ;
     RECT  2.16 44.415 19.44 44.685 ;
     RECT  2.16 44.955 19.44 45.225 ;
     RECT  2.16 45.495 19.44 45.765 ;
     RECT  2.16 46.035 19.44 46.305 ;
     RECT  2.16 46.575 19.44 46.845 ;
     RECT  2.16 47.115 19.44 47.385 ;
     RECT  2.16 47.655 19.44 47.925 ;
     RECT  2.16 48.195 19.44 48.465 ;
     RECT  2.16 48.735 19.44 49.005 ;
     RECT  2.16 49.275 19.44 49.545 ;
     RECT  2.16 49.815 19.44 50.085 ;
     RECT  2.16 50.355 19.44 50.625 ;
     RECT  2.16 50.895 19.44 51.165 ;
     RECT  2.16 51.435 19.44 51.705 ;
    LAYER M1 ;
     RECT  2.16 2.151 19.44 51.849 ;
    LAYER M2 ;
     RECT  0.031 24.786 0.067 24.804 ;
     RECT  0.031 21.546 0.103 21.564 ;
     RECT  0.067 24.786 0.103 25.344 ;
     RECT  0.031 28.26 0.103 28.278 ;
     RECT  0.067 30.114 0.103 30.294 ;
     RECT  0.031 31.194 0.103 31.212 ;
     RECT  0.031 32.238 0.103 32.256 ;
     RECT  0.067 37.746 0.103 37.764 ;
     RECT  0.067 39.762 0.103 39.78 ;
     RECT  0.031 40.761 0.103 40.779 ;
     RECT  0.103 39.186 0.131 40.779 ;
     RECT  0.103 21.546 0.139 22.806 ;
     RECT  0.103 34.704 0.139 35.334 ;
     RECT  0.103 36.441 0.139 38.124 ;
     RECT  0.131 39.186 0.139 40.464 ;
     RECT  0.067 26.262 0.167 26.28 ;
     RECT  0.103 28.26 0.167 30.294 ;
     RECT  0.067 42.84 0.167 42.858 ;
     RECT  0.139 21.546 0.175 23.184 ;
     RECT  0.175 19.854 0.211 19.872 ;
     RECT  0.175 20.97 0.211 23.184 ;
     RECT  0.067 18.126 0.239 18.144 ;
     RECT  0.167 28.566 0.283 30.294 ;
     RECT  0.103 31.194 0.283 32.994 ;
     RECT  0.283 28.566 0.355 32.994 ;
     RECT  0.211 19.854 0.419 23.184 ;
     RECT  0.355 28.566 0.427 33.102 ;
     RECT  0.419 19.854 0.535 22.194 ;
     RECT  0.419 23.13 0.535 23.184 ;
     RECT  0.175 41.796 0.535 41.814 ;
     RECT  0.211 42.606 0.535 42.624 ;
     RECT  0.103 24.246 0.859 25.344 ;
     RECT  0.859 24.246 0.895 25.929 ;
     RECT  0.535 23.13 1.003 23.346 ;
     RECT  0.895 24.174 1.003 25.929 ;
     RECT  0.427 28.566 1.291 33.534 ;
     RECT  0.139 34.506 1.291 40.464 ;
     RECT  1.003 23.13 1.399 25.929 ;
     RECT  1.651 18.54 1.687 18.558 ;
     RECT  1.615 27.072 1.723 27.09 ;
     RECT  1.291 27.954 1.723 40.464 ;
     RECT  1.399 23.13 1.759 26.154 ;
     RECT  1.723 27.072 1.759 40.464 ;
     RECT  1.687 18.162 2.011 18.558 ;
     RECT  1.975 16.272 2.047 16.29 ;
     RECT  0.535 19.656 2.119 22.194 ;
     RECT  1.759 23.13 2.119 40.464 ;
     RECT  2.047 15.84 2.16 16.29 ;
     RECT  2.011 17.622 2.16 18.558 ;
     RECT  2.119 19.656 2.16 40.464 ;
     RECT  0.535 41.796 2.16 42.624 ;
     RECT  2.16 2.151 19.44 51.849 ;
     RECT  19.44 22.86 19.931 35.334 ;
     RECT  19.931 22.86 19.967 35.262 ;
     RECT  19.44 41.886 20.219 41.904 ;
     RECT  19.967 28.422 20.327 29.826 ;
     RECT  19.967 30.618 20.435 35.262 ;
     RECT  19.967 22.86 20.507 25.542 ;
     RECT  19.967 26.37 20.507 27.36 ;
     RECT  20.327 28.422 20.507 28.818 ;
     RECT  20.327 29.574 20.507 29.826 ;
     RECT  20.435 30.618 20.507 32.634 ;
     RECT  20.435 33.588 20.507 35.262 ;
     RECT  20.507 22.86 20.543 23.346 ;
     RECT  20.507 24.516 20.543 25.542 ;
     RECT  20.507 32.616 20.543 32.634 ;
     RECT  20.507 26.37 20.579 27.234 ;
     RECT  20.507 33.858 21.415 33.876 ;
     RECT  20.507 35.01 21.443 35.262 ;
     RECT  20.543 24.786 21.479 25.542 ;
     RECT  20.507 31.23 21.479 31.824 ;
     RECT  21.443 35.01 21.479 35.154 ;
     RECT  19.44 20.124 21.515 20.718 ;
     RECT  20.543 23.328 21.515 23.346 ;
     RECT  21.479 24.786 21.515 25.506 ;
     RECT  20.579 26.37 21.515 26.694 ;
     RECT  21.415 27.486 21.515 27.504 ;
     RECT  20.507 29.574 21.515 29.592 ;
     RECT  21.479 31.23 21.515 31.752 ;
     RECT  21.415 33.858 21.515 34.074 ;
     RECT  21.479 35.136 21.515 35.154 ;
    LAYER M3 ;
     RECT  2.415 2.143 2.505 2.413 ;
     RECT  5.115 2.143 5.205 2.413 ;
     RECT  7.815 2.143 7.905 2.413 ;
     RECT  10.515 2.143 10.605 2.413 ;
     RECT  13.215 2.143 13.305 2.413 ;
     RECT  15.915 2.143 16.005 2.413 ;
     RECT  18.615 2.143 18.705 2.413 ;
     RECT  2.415 2.413 2.697 15.691 ;
     RECT  2.304 15.691 2.697 15.787 ;
     RECT  2.304 15.787 2.754 15.835 ;
     RECT  2.052 15.835 2.754 16.231 ;
     RECT  2.052 16.231 2.826 16.267 ;
     RECT  3.708 16.105 3.726 16.315 ;
     RECT  0.144 16.171 0.162 16.349 ;
     RECT  1.98 16.267 2.826 16.363 ;
     RECT  3.708 16.315 4.266 16.363 ;
     RECT  0.9 16.555 0.918 16.843 ;
     RECT  1.98 16.363 4.266 16.843 ;
     RECT  0.108 16.939 0.126 17.227 ;
     RECT  0.9 16.843 4.266 17.227 ;
     RECT  0.108 17.227 4.266 18.121 ;
     RECT  0.072 18.121 4.266 18.187 ;
     RECT  6.804 19.471 6.822 19.679 ;
     RECT  14.868 19.471 14.886 20.011 ;
     RECT  21.492 19.915 21.51 20.011 ;
     RECT  14.832 20.011 15.138 20.047 ;
     RECT  15.915 2.413 16.197 20.047 ;
     RECT  18.615 2.413 18.897 20.083 ;
     RECT  14.832 20.047 16.197 20.155 ;
     RECT  21.456 20.011 21.51 20.183 ;
     RECT  18.432 20.083 19.422 20.191 ;
     RECT  14.832 20.155 16.686 20.203 ;
     RECT  18.036 20.191 19.422 20.333 ;
     RECT  13.215 2.413 13.497 20.389 ;
     RECT  13.215 20.389 13.914 20.429 ;
     RECT  14.796 20.203 16.686 20.453 ;
     RECT  18.036 20.333 19.134 20.453 ;
     RECT  18.036 20.453 18.897 20.461 ;
     RECT  15.372 20.453 16.686 20.477 ;
     RECT  15.696 20.477 16.686 20.581 ;
     RECT  17.676 20.461 18.897 20.581 ;
     RECT  10.515 2.413 10.797 20.587 ;
     RECT  20.484 20.395 20.502 20.587 ;
     RECT  15.696 20.581 18.897 20.621 ;
     RECT  19.908 20.587 20.502 20.651 ;
     RECT  10.515 20.587 10.818 20.687 ;
     RECT  19.908 20.651 20.214 20.687 ;
     RECT  21.492 20.183 21.51 20.723 ;
     RECT  0.072 18.187 4.374 20.731 ;
     RECT  5.115 2.413 5.397 20.731 ;
     RECT  12.276 20.695 12.294 20.813 ;
     RECT  15.696 20.621 16.722 20.849 ;
     RECT  6.84 20.011 6.858 20.885 ;
     RECT  14.256 20.461 14.274 20.885 ;
     RECT  15.696 20.849 16.506 20.993 ;
     RECT  15.696 20.993 16.197 21.005 ;
     RECT  17.676 20.621 18.897 21.119 ;
     RECT  7.056 21.091 7.074 21.191 ;
     RECT  0.072 20.731 5.397 21.541 ;
     RECT  0.036 21.541 5.397 21.811 ;
     RECT  8.856 21.811 8.874 21.901 ;
     RECT  15.915 21.005 16.197 21.901 ;
     RECT  0.036 21.811 5.886 21.929 ;
     RECT  8.856 21.901 8.946 22.001 ;
     RECT  13.215 20.429 13.497 22.081 ;
     RECT  13.176 22.081 13.497 22.171 ;
     RECT  0.036 21.929 5.814 22.235 ;
     RECT  7.02 22.315 7.038 22.351 ;
     RECT  7.815 2.413 8.097 22.351 ;
     RECT  7.02 22.351 8.097 22.441 ;
     RECT  12.564 22.171 13.497 22.441 ;
     RECT  17.676 21.119 17.694 22.477 ;
     RECT  7.02 22.441 8.442 22.513 ;
     RECT  17.676 22.477 17.766 22.585 ;
     RECT  17.676 22.585 17.802 22.621 ;
     RECT  18.615 21.119 18.897 22.621 ;
     RECT  17.676 22.621 18.897 22.711 ;
     RECT  15.915 21.901 16.65 22.747 ;
     RECT  17.388 22.711 18.897 22.747 ;
     RECT  6.84 22.513 8.442 22.819 ;
     RECT  9.18 22.585 9.198 22.819 ;
     RECT  15.915 22.747 18.99 22.819 ;
     RECT  20.196 20.687 20.214 22.855 ;
     RECT  15.84 22.819 18.99 22.891 ;
     RECT  0.036 22.235 5.742 22.981 ;
     RECT  12.24 22.441 13.497 22.981 ;
     RECT  6.84 22.819 9.234 23.053 ;
     RECT  12.24 22.981 13.554 23.053 ;
     RECT  6.84 23.053 9.27 23.081 ;
     RECT  7.815 23.081 9.27 23.189 ;
     RECT  14.796 22.939 14.814 23.227 ;
     RECT  0.036 22.981 6.066 23.251 ;
     RECT  6.84 23.081 6.858 23.251 ;
     RECT  12.24 23.053 13.626 23.287 ;
     RECT  14.4 23.227 14.814 23.287 ;
     RECT  20.196 22.855 20.538 23.309 ;
     RECT  0.036 23.251 6.858 23.315 ;
     RECT  8.892 23.189 9.234 23.315 ;
     RECT  12.24 23.287 14.814 23.323 ;
     RECT  15.588 22.891 19.026 23.323 ;
     RECT  21.492 23.179 21.51 23.351 ;
     RECT  20.196 23.309 20.502 23.371 ;
     RECT  8.892 23.315 9.198 23.387 ;
     RECT  10.515 20.687 10.797 23.431 ;
     RECT  0.036 23.315 5.994 23.501 ;
     RECT  10.116 23.431 10.797 23.629 ;
     RECT  6.768 23.315 6.858 23.827 ;
     RECT  9.972 23.629 10.797 23.855 ;
     RECT  6.768 23.827 7.074 23.927 ;
     RECT  0.864 23.501 5.994 24.091 ;
     RECT  12.24 23.323 19.026 24.133 ;
     RECT  19.908 23.371 20.502 24.133 ;
     RECT  0.036 23.501 0.126 24.235 ;
     RECT  0.864 24.091 6.03 24.235 ;
     RECT  0.036 24.235 6.03 24.241 ;
     RECT  6.768 23.927 6.858 24.241 ;
     RECT  12.24 24.133 20.502 24.467 ;
     RECT  12.24 24.467 18.897 24.475 ;
     RECT  19.908 24.467 20.502 24.511 ;
     RECT  0.036 24.241 6.858 24.745 ;
     RECT  0.036 24.745 6.966 24.809 ;
     RECT  19.908 24.511 20.538 24.845 ;
     RECT  12.168 24.475 18.897 24.899 ;
     RECT  9.144 23.387 9.198 24.907 ;
     RECT  9.144 24.907 9.234 25.007 ;
     RECT  9.144 25.007 9.162 25.079 ;
     RECT  0.072 24.809 6.966 25.141 ;
     RECT  7.815 23.189 8.097 25.141 ;
     RECT  12.168 24.899 13.662 25.141 ;
     RECT  14.508 24.899 18.897 25.213 ;
     RECT  19.908 24.845 20.43 25.241 ;
     RECT  0.072 25.141 8.097 25.313 ;
     RECT  10.515 23.855 10.797 25.321 ;
     RECT  0.072 25.313 6.03 25.349 ;
     RECT  21.492 24.619 21.51 25.387 ;
     RECT  21.456 25.387 21.51 25.511 ;
     RECT  21.456 25.511 21.474 25.547 ;
     RECT  19.908 25.241 20.214 25.579 ;
     RECT  14.508 25.213 19.026 25.583 ;
     RECT  12.024 25.141 13.662 25.717 ;
     RECT  14.508 25.583 14.85 25.717 ;
     RECT  19.872 25.579 20.214 25.771 ;
     RECT  15.66 25.583 19.026 25.861 ;
     RECT  19.836 25.771 20.214 25.861 ;
     RECT  6.768 25.313 7.002 26.159 ;
     RECT  0.108 25.349 6.03 26.257 ;
     RECT  12.024 25.717 14.85 26.365 ;
     RECT  15.66 25.861 20.214 26.365 ;
     RECT  6.768 26.159 6.786 26.429 ;
     RECT  12.024 26.365 20.214 26.539 ;
     RECT  21.492 26.251 21.51 26.635 ;
     RECT  21.312 26.635 21.51 26.699 ;
     RECT  10.515 25.321 10.926 26.761 ;
     RECT  12.024 26.539 20.25 26.761 ;
     RECT  10.515 26.761 20.25 26.765 ;
     RECT  21.312 26.699 21.33 26.765 ;
     RECT  12.276 26.765 20.25 26.789 ;
     RECT  17.856 26.789 20.25 26.824 ;
     RECT  12.276 26.789 17.082 26.861 ;
     RECT  17.856 26.824 20.502 27.053 ;
     RECT  17.928 27.053 20.502 27.211 ;
     RECT  6.912 27.139 6.93 27.239 ;
     RECT  14.868 26.861 17.082 27.239 ;
     RECT  17.928 27.211 20.574 27.329 ;
     RECT  10.515 26.765 11.43 27.437 ;
     RECT  18.036 27.329 20.574 27.437 ;
     RECT  21.42 27.451 21.438 27.481 ;
     RECT  21.42 27.481 21.51 27.509 ;
     RECT  21.492 27.509 21.51 27.533 ;
     RECT  12.276 26.861 14.022 27.571 ;
     RECT  12.24 27.571 14.022 27.635 ;
     RECT  14.868 27.239 17.01 27.715 ;
     RECT  12.24 27.635 13.734 27.835 ;
     RECT  0.072 26.257 6.03 27.869 ;
     RECT  14.544 27.715 17.01 27.869 ;
     RECT  12.132 27.835 13.734 27.875 ;
     RECT  16.92 27.869 17.01 28.021 ;
     RECT  14.544 27.869 16.197 28.139 ;
     RECT  18.036 27.437 20.214 28.147 ;
     RECT  16.92 28.021 17.118 28.175 ;
     RECT  0.072 27.869 5.634 28.255 ;
     RECT  16.956 28.175 17.118 28.291 ;
     RECT  12.24 27.875 13.734 28.381 ;
     RECT  14.544 28.139 14.994 28.381 ;
     RECT  0.036 28.255 5.634 28.409 ;
     RECT  17.964 28.147 20.214 28.417 ;
     RECT  16.956 28.291 17.226 28.445 ;
     RECT  6.84 28.147 6.858 28.651 ;
     RECT  6.768 28.651 6.858 28.687 ;
     RECT  10.515 27.437 10.926 28.687 ;
     RECT  17.1 28.445 17.226 28.687 ;
     RECT  17.964 28.417 20.502 28.687 ;
     RECT  6.768 28.687 6.93 28.787 ;
     RECT  17.1 28.687 20.502 28.823 ;
     RECT  10.515 28.687 10.998 28.859 ;
     RECT  12.24 28.381 14.994 28.877 ;
     RECT  12.24 28.877 14.85 28.939 ;
     RECT  11.988 28.939 14.85 28.985 ;
     RECT  17.1 28.823 20.322 29.057 ;
     RECT  17.1 29.057 17.226 29.191 ;
     RECT  6.768 28.787 6.894 29.227 ;
     RECT  15.768 28.139 16.197 29.227 ;
     RECT  16.992 29.191 17.226 29.227 ;
     RECT  0.036 28.409 5.397 29.371 ;
     RECT  15.768 29.227 17.226 29.371 ;
     RECT  12.024 28.985 14.85 29.597 ;
     RECT  21.492 29.419 21.51 29.597 ;
     RECT  0.036 29.371 5.814 29.641 ;
     RECT  6.66 29.227 6.894 29.641 ;
     RECT  13.104 29.597 14.85 29.659 ;
     RECT  15.624 29.371 17.226 29.659 ;
     RECT  0.036 29.641 6.894 29.767 ;
     RECT  18.072 29.057 20.322 29.803 ;
     RECT  0.036 29.767 6.93 29.875 ;
     RECT  13.104 29.659 17.226 29.911 ;
     RECT  18.072 29.803 20.502 29.911 ;
     RECT  12.024 29.597 12.33 30.029 ;
     RECT  13.104 29.911 20.502 30.137 ;
     RECT  14.472 30.137 20.502 30.173 ;
     RECT  0.036 29.875 7.002 30.379 ;
     RECT  7.815 25.313 8.097 30.379 ;
     RECT  12.276 30.029 12.33 30.379 ;
     RECT  13.104 30.137 13.497 30.379 ;
     RECT  14.58 30.173 20.502 30.509 ;
     RECT  0.036 30.379 8.097 30.569 ;
     RECT  18.144 30.509 20.502 30.641 ;
     RECT  12.276 30.379 13.497 30.859 ;
     RECT  12.096 30.859 13.497 30.911 ;
     RECT  18.144 30.641 20.43 30.989 ;
     RECT  7.815 30.569 8.097 31.081 ;
     RECT  12.24 30.911 13.497 31.109 ;
     RECT  7.815 31.081 8.73 31.181 ;
     RECT  0.036 30.569 5.526 31.217 ;
     RECT  12.348 31.109 13.497 31.217 ;
     RECT  21.492 30.763 21.51 31.243 ;
     RECT  14.58 30.509 17.334 31.339 ;
     RECT  18.144 30.989 19.422 31.339 ;
     RECT  0.072 31.217 5.526 31.351 ;
     RECT  6.66 30.569 6.894 31.351 ;
     RECT  14.58 31.339 19.422 31.373 ;
     RECT  0.072 31.351 6.894 31.387 ;
     RECT  7.815 31.181 8.154 31.387 ;
     RECT  10.515 28.859 10.926 31.483 ;
     RECT  14.58 31.373 18.954 31.621 ;
     RECT  14.364 31.621 18.954 31.757 ;
     RECT  21.456 31.243 21.51 31.757 ;
     RECT  20.196 30.989 20.43 31.819 ;
     RECT  21.456 31.757 21.474 31.829 ;
     RECT  19.872 31.819 20.43 31.915 ;
     RECT  9.036 31.351 9.162 31.919 ;
     RECT  10.44 31.483 10.926 31.919 ;
     RECT  12.348 31.217 12.366 31.963 ;
     RECT  0.072 31.387 8.154 32.035 ;
     RECT  13.104 31.217 13.497 32.071 ;
     RECT  14.364 31.757 18.897 32.071 ;
     RECT  0.072 32.035 8.514 32.233 ;
     RECT  0.036 32.233 8.514 32.261 ;
     RECT  11.952 31.963 12.366 32.269 ;
     RECT  13.104 32.071 18.897 32.269 ;
     RECT  0.036 32.261 6.93 32.459 ;
     RECT  6.912 32.459 6.93 32.495 ;
     RECT  11.952 32.269 18.897 32.495 ;
     RECT  19.872 31.915 20.502 32.611 ;
     RECT  18.216 32.495 18.897 32.639 ;
     RECT  11.952 32.495 17.406 32.873 ;
     RECT  19.872 32.611 20.538 32.873 ;
     RECT  19.944 32.873 20.538 32.909 ;
     RECT  18.288 32.639 18.897 33.007 ;
     RECT  10.515 31.919 10.854 33.071 ;
     RECT  18.288 33.007 19.17 33.143 ;
     RECT  7.815 32.261 8.514 33.151 ;
     RECT  7.128 33.151 8.694 33.241 ;
     RECT  7.128 33.241 8.766 33.269 ;
     RECT  12.276 32.873 17.406 33.385 ;
     RECT  18.288 33.143 18.918 33.385 ;
     RECT  7.815 33.269 8.766 33.413 ;
     RECT  12.276 33.385 18.918 33.611 ;
     RECT  6.264 33.313 6.282 33.691 ;
     RECT  19.944 32.909 20.502 33.739 ;
     RECT  6.12 33.691 6.282 33.809 ;
     RECT  10.515 33.071 10.797 33.853 ;
     RECT  12.672 33.611 18.918 33.869 ;
     RECT  19.908 33.739 20.502 33.953 ;
     RECT  0.036 32.459 5.397 33.961 ;
     RECT  9.18 33.889 9.198 33.989 ;
     RECT  21.492 33.835 21.51 34.051 ;
     RECT  0.036 33.961 5.814 34.151 ;
     RECT  10.515 33.853 11.43 34.259 ;
     RECT  12.816 33.869 18.918 34.315 ;
     RECT  12.816 34.315 19.386 34.349 ;
     RECT  20.196 33.953 20.502 34.655 ;
     RECT  20.196 34.655 20.466 34.691 ;
     RECT  21.42 34.051 21.51 34.795 ;
     RECT  10.515 34.259 10.854 34.799 ;
     RECT  12.888 34.349 19.386 34.889 ;
     RECT  12.888 34.889 13.986 34.925 ;
     RECT  21.312 34.795 21.51 34.925 ;
     RECT  9.144 34.501 9.162 34.969 ;
     RECT  14.94 34.889 15.102 35.159 ;
     RECT  15.84 34.889 19.386 35.159 ;
     RECT  21.42 34.925 21.51 35.159 ;
     RECT  18.615 35.159 19.386 35.179 ;
     RECT  20.196 34.691 20.214 35.179 ;
     RECT  9.144 34.969 9.198 35.267 ;
     RECT  21.42 35.159 21.438 35.267 ;
     RECT  12.888 34.925 13.698 35.323 ;
     RECT  6.84 35.167 6.858 35.339 ;
     RECT  9.18 35.267 9.198 35.339 ;
     RECT  15.84 35.159 17.658 35.339 ;
     RECT  18.615 35.179 20.214 35.339 ;
     RECT  15.084 35.159 15.102 35.429 ;
     RECT  18.615 35.339 19.386 35.501 ;
     RECT  16.956 35.339 17.658 35.573 ;
     RECT  16.956 35.573 16.974 35.699 ;
     RECT  10.515 34.799 10.797 35.707 ;
     RECT  12.384 35.323 13.698 35.741 ;
     RECT  13.215 35.741 13.698 35.771 ;
     RECT  15.84 35.339 16.197 35.879 ;
     RECT  10.515 35.707 10.854 35.969 ;
     RECT  12.06 35.792 12.078 36.029 ;
     RECT  14.256 35.851 14.274 36.041 ;
     RECT  0.036 34.151 5.397 38.573 ;
     RECT  1.62 38.573 5.397 38.579 ;
     RECT  1.62 38.579 4.302 38.777 ;
     RECT  1.692 38.777 4.302 40.055 ;
     RECT  1.692 40.055 4.23 40.325 ;
     RECT  0.036 38.573 0.558 40.589 ;
     RECT  0.036 40.589 0.126 40.784 ;
     RECT  1.98 40.325 4.23 40.865 ;
     RECT  0.072 40.784 0.126 41.467 ;
     RECT  1.98 40.865 3.114 41.881 ;
     RECT  4.212 40.865 4.23 41.881 ;
     RECT  20.196 35.339 20.214 41.909 ;
     RECT  1.98 41.881 4.23 41.945 ;
     RECT  0.072 41.467 0.63 41.995 ;
     RECT  0.072 41.995 0.666 42.283 ;
     RECT  0.072 42.283 0.954 42.413 ;
     RECT  0.072 42.413 0.666 42.863 ;
     RECT  0.144 42.863 0.666 42.893 ;
     RECT  0.18 42.893 0.666 42.989 ;
     RECT  1.98 41.945 3.87 43.141 ;
     RECT  0.216 42.989 0.666 43.277 ;
     RECT  1.98 43.141 4.194 43.295 ;
     RECT  4.176 43.295 4.194 43.331 ;
     RECT  0.216 43.277 0.594 43.373 ;
     RECT  1.98 43.295 3.222 43.469 ;
     RECT  0.252 43.373 0.594 43.565 ;
     RECT  0.252 43.565 0.27 43.661 ;
     RECT  2.304 43.469 3.222 44.105 ;
     RECT  2.304 44.105 2.697 44.177 ;
     RECT  2.415 44.177 2.697 51.587 ;
     RECT  5.115 38.579 5.397 51.587 ;
     RECT  7.815 33.413 8.097 51.587 ;
     RECT  10.515 35.969 10.797 51.587 ;
     RECT  13.215 35.771 13.497 51.587 ;
     RECT  15.915 35.879 16.197 51.587 ;
     RECT  18.615 35.501 18.897 51.587 ;
     RECT  2.415 51.587 2.505 51.857 ;
     RECT  5.115 51.587 5.205 51.857 ;
     RECT  7.815 51.587 7.905 51.857 ;
     RECT  10.515 51.587 10.605 51.857 ;
     RECT  13.215 51.587 13.305 51.857 ;
     RECT  15.915 51.587 16.005 51.857 ;
     RECT  18.615 51.587 18.705 51.857 ;
    LAYER M4 ;
     RECT  0.084 42.192 0.241 42.216 ;
     RECT  0.06 42.216 0.241 42.288 ;
     RECT  0.084 42.288 0.241 42.312 ;
     RECT  0.06 42.312 0.241 42.384 ;
     RECT  0.084 42.384 0.241 42.408 ;
     RECT  0.06 42.408 0.241 42.48 ;
     RECT  0.084 42.48 0.241 42.504 ;
     RECT  0.06 42.504 0.241 42.576 ;
     RECT  0.084 42.576 0.241 42.6 ;
     RECT  0.06 42.6 0.241 42.672 ;
     RECT  0.084 42.672 0.241 42.696 ;
     RECT  0.06 42.696 0.241 42.768 ;
     RECT  0.084 42.768 0.241 42.792 ;
     RECT  0.06 42.792 0.241 42.864 ;
     RECT  0.084 42.864 0.241 42.888 ;
     RECT  0.06 42.888 0.241 42.96 ;
     RECT  0.084 42.96 0.241 42.984 ;
     RECT  0.06 42.984 0.241 43.056 ;
     RECT  0.084 43.056 0.241 43.08 ;
     RECT  0.06 43.08 0.241 43.152 ;
     RECT  0.084 43.152 0.241 43.176 ;
     RECT  0.06 43.176 0.241 43.248 ;
     RECT  0.084 43.248 0.241 43.272 ;
     RECT  0.06 43.272 0.241 43.344 ;
     RECT  0.084 43.344 0.241 43.368 ;
     RECT  0.06 43.368 0.241 43.44 ;
     RECT  0.084 43.44 0.241 43.464 ;
     RECT  0.06 43.464 0.241 43.536 ;
     RECT  0.084 43.536 0.241 43.56 ;
     RECT  0.06 43.56 0.241 43.632 ;
     RECT  0.084 43.632 0.241 43.656 ;
     RECT  0.06 43.656 0.241 43.728 ;
     RECT  0.084 43.728 0.241 43.752 ;
     RECT  0.06 43.752 0.241 43.824 ;
     RECT  0.084 43.824 0.241 43.848 ;
     RECT  0.06 43.848 0.241 43.92 ;
     RECT  0.084 43.92 0.241 43.944 ;
     RECT  0.06 43.944 0.241 44.016 ;
     RECT  0.084 44.016 0.241 44.04 ;
     RECT  0.084 15.696 0.601 15.72 ;
     RECT  0.06 15.72 0.601 15.792 ;
     RECT  0.084 15.792 0.601 15.816 ;
     RECT  0.06 15.816 0.601 15.888 ;
     RECT  0.084 15.888 0.601 15.912 ;
     RECT  0.06 15.912 0.601 15.984 ;
     RECT  0.084 15.984 0.601 16.008 ;
     RECT  0.06 16.008 0.601 16.08 ;
     RECT  0.084 16.08 0.601 16.104 ;
     RECT  0.06 16.104 0.601 16.176 ;
     RECT  0.084 16.176 0.601 16.2 ;
     RECT  0.06 16.2 0.601 16.272 ;
     RECT  0.084 16.272 0.601 16.296 ;
     RECT  0.06 16.296 0.601 16.368 ;
     RECT  0.084 16.368 0.601 16.392 ;
     RECT  0.06 16.392 0.601 16.464 ;
     RECT  0.084 16.464 0.601 16.488 ;
     RECT  0.06 16.488 0.601 16.56 ;
     RECT  0.084 16.56 0.601 16.584 ;
     RECT  0.06 16.584 0.601 16.656 ;
     RECT  0.084 16.656 0.601 16.68 ;
     RECT  0.06 16.68 0.601 16.752 ;
     RECT  0.084 16.752 0.601 16.776 ;
     RECT  0.06 16.776 0.601 16.848 ;
     RECT  0.084 16.848 0.601 16.872 ;
     RECT  0.06 16.872 0.601 16.944 ;
     RECT  0.084 16.944 0.601 16.968 ;
     RECT  0.06 16.968 0.601 17.04 ;
     RECT  0.084 17.04 0.601 17.064 ;
     RECT  0.06 17.064 0.601 17.136 ;
     RECT  0.084 17.136 0.601 17.16 ;
     RECT  0.06 17.16 0.601 17.232 ;
     RECT  0.084 17.232 0.601 17.256 ;
     RECT  0.06 17.256 0.601 17.328 ;
     RECT  0.084 17.328 0.601 17.352 ;
     RECT  0.06 17.352 0.601 17.424 ;
     RECT  0.084 17.424 0.601 17.448 ;
     RECT  0.06 17.448 0.601 17.52 ;
     RECT  0.084 17.52 0.601 17.544 ;
     RECT  0.06 17.544 0.601 17.616 ;
     RECT  0.084 17.616 0.601 17.64 ;
     RECT  0.06 17.64 0.601 17.712 ;
     RECT  0.084 17.712 0.601 17.736 ;
     RECT  0.06 17.736 0.601 17.808 ;
     RECT  0.084 17.808 0.601 17.832 ;
     RECT  0.06 17.832 0.601 17.904 ;
     RECT  0.084 17.904 0.601 17.928 ;
     RECT  0.06 17.928 0.601 18 ;
     RECT  0.084 18 0.601 18.024 ;
     RECT  0.06 18.024 0.601 18.096 ;
     RECT  0.084 18.096 0.601 18.12 ;
     RECT  0.06 18.12 0.601 18.192 ;
     RECT  0.084 18.192 0.601 18.216 ;
     RECT  0.06 18.216 0.601 18.288 ;
     RECT  0.084 18.288 0.601 18.312 ;
     RECT  0.06 18.312 0.601 18.384 ;
     RECT  0.084 18.384 0.601 18.408 ;
     RECT  0.06 18.408 0.601 18.48 ;
     RECT  0.084 18.48 0.601 18.504 ;
     RECT  0.06 18.504 0.601 18.576 ;
     RECT  0.084 18.576 0.601 18.6 ;
     RECT  0.06 18.6 0.601 18.672 ;
     RECT  0.084 18.672 0.601 18.696 ;
     RECT  0.06 18.696 0.601 18.768 ;
     RECT  0.084 18.768 0.601 18.792 ;
     RECT  0.06 18.792 0.601 18.864 ;
     RECT  0.084 18.864 0.601 18.888 ;
     RECT  0.06 18.888 0.601 18.96 ;
     RECT  0.084 18.96 0.601 18.984 ;
     RECT  0.06 18.984 0.601 19.056 ;
     RECT  0.084 19.056 0.601 19.08 ;
     RECT  0.06 19.08 0.601 19.152 ;
     RECT  0.084 19.152 0.601 19.176 ;
     RECT  0.06 19.176 0.601 19.248 ;
     RECT  0.084 19.248 0.601 19.272 ;
     RECT  0.06 19.272 0.601 19.344 ;
     RECT  0.084 19.344 0.601 19.368 ;
     RECT  0.06 19.368 0.601 19.44 ;
     RECT  0.084 19.44 0.601 19.464 ;
     RECT  0.06 19.464 0.601 19.536 ;
     RECT  0.084 19.536 0.601 19.56 ;
     RECT  0.06 19.56 0.601 19.632 ;
     RECT  0.084 19.632 0.601 19.656 ;
     RECT  0.06 19.656 0.601 19.728 ;
     RECT  0.084 19.728 0.601 19.752 ;
     RECT  0.06 19.752 0.601 19.824 ;
     RECT  0.084 19.824 0.601 19.848 ;
     RECT  0.06 19.848 0.601 19.92 ;
     RECT  0.084 19.92 0.601 19.944 ;
     RECT  0.06 19.944 0.601 20.016 ;
     RECT  0.084 20.016 0.601 20.04 ;
     RECT  0.06 20.04 0.601 20.112 ;
     RECT  0.084 20.112 0.601 20.136 ;
     RECT  0.06 20.136 0.601 20.208 ;
     RECT  0.084 20.208 0.601 20.232 ;
     RECT  0.06 20.232 0.601 20.304 ;
     RECT  0.084 20.304 0.601 20.328 ;
     RECT  0.06 20.328 0.601 20.4 ;
     RECT  0.084 20.4 0.601 20.424 ;
     RECT  0.06 20.424 0.601 20.496 ;
     RECT  0.084 20.496 0.601 20.52 ;
     RECT  0.06 20.52 0.601 20.592 ;
     RECT  0.084 20.592 0.601 20.616 ;
     RECT  0.06 20.616 0.601 20.688 ;
     RECT  0.084 20.688 0.601 20.712 ;
     RECT  0.06 20.712 0.601 20.784 ;
     RECT  0.084 20.784 0.601 20.808 ;
     RECT  0.06 20.808 0.601 20.88 ;
     RECT  0.084 20.88 0.601 20.904 ;
     RECT  0.06 20.904 0.601 20.976 ;
     RECT  0.084 20.976 0.601 21 ;
     RECT  0.06 21 0.601 21.072 ;
     RECT  0.084 21.072 0.601 21.096 ;
     RECT  0.06 21.096 0.601 21.168 ;
     RECT  0.084 21.168 0.601 21.192 ;
     RECT  0.06 21.192 0.601 21.264 ;
     RECT  0.084 21.264 0.601 21.288 ;
     RECT  0.06 21.288 0.601 21.36 ;
     RECT  0.084 21.36 0.601 21.384 ;
     RECT  0.06 21.384 0.601 21.456 ;
     RECT  0.084 21.456 0.601 21.48 ;
     RECT  0.06 21.48 0.601 21.552 ;
     RECT  0.084 21.552 0.601 21.576 ;
     RECT  0.06 21.576 0.601 21.648 ;
     RECT  0.084 21.648 0.601 21.672 ;
     RECT  0.06 21.672 0.601 21.744 ;
     RECT  0.084 21.744 0.601 21.768 ;
     RECT  0.06 21.768 0.601 21.84 ;
     RECT  0.084 21.84 0.601 21.864 ;
     RECT  0.06 21.864 0.601 21.936 ;
     RECT  0.084 21.936 0.601 21.96 ;
     RECT  0.06 21.96 0.601 22.032 ;
     RECT  0.084 22.032 0.601 22.056 ;
     RECT  0.06 22.056 0.601 22.128 ;
     RECT  0.084 22.128 0.601 22.152 ;
     RECT  0.06 22.152 0.601 22.224 ;
     RECT  0.084 22.224 0.601 22.248 ;
     RECT  0.06 22.248 0.601 22.32 ;
     RECT  0.084 22.32 0.601 22.344 ;
     RECT  0.06 22.344 0.601 22.416 ;
     RECT  0.084 22.416 0.601 22.44 ;
     RECT  0.06 22.44 0.601 22.512 ;
     RECT  0.084 22.512 0.601 22.536 ;
     RECT  0.06 22.536 0.601 22.608 ;
     RECT  0.084 22.608 0.601 22.632 ;
     RECT  0.06 22.632 0.601 22.704 ;
     RECT  0.084 22.704 0.601 22.728 ;
     RECT  0.06 22.728 0.601 22.8 ;
     RECT  0.084 22.8 0.601 22.824 ;
     RECT  0.06 22.824 0.601 22.896 ;
     RECT  0.084 22.896 0.601 22.92 ;
     RECT  0.06 22.92 0.601 22.992 ;
     RECT  0.084 22.992 0.601 23.016 ;
     RECT  0.06 23.016 0.601 23.088 ;
     RECT  0.084 23.088 0.601 23.112 ;
     RECT  0.06 23.112 0.601 23.184 ;
     RECT  0.084 23.184 0.601 23.208 ;
     RECT  0.06 23.208 0.601 23.28 ;
     RECT  0.084 23.28 0.601 23.304 ;
     RECT  0.06 23.304 0.601 23.376 ;
     RECT  0.084 23.376 0.601 23.4 ;
     RECT  0.06 23.4 0.601 23.472 ;
     RECT  0.084 23.472 0.601 23.496 ;
     RECT  0.06 23.496 0.601 23.568 ;
     RECT  0.084 23.568 0.601 23.592 ;
     RECT  0.06 23.592 0.601 23.664 ;
     RECT  0.084 23.664 0.601 23.688 ;
     RECT  0.06 23.688 0.601 23.76 ;
     RECT  0.084 23.76 0.601 23.784 ;
     RECT  0.06 23.784 0.601 23.856 ;
     RECT  0.084 23.856 0.601 23.88 ;
     RECT  0.06 23.88 0.601 23.952 ;
     RECT  0.084 23.952 0.601 23.976 ;
     RECT  0.06 23.976 0.601 24.048 ;
     RECT  0.084 24.048 0.601 24.072 ;
     RECT  0.06 24.072 0.601 24.144 ;
     RECT  0.084 24.144 0.601 24.168 ;
     RECT  0.06 24.168 0.601 24.24 ;
     RECT  0.084 24.24 0.601 24.264 ;
     RECT  0.06 24.264 0.601 24.336 ;
     RECT  0.084 24.336 0.601 24.36 ;
     RECT  0.06 24.36 0.601 24.432 ;
     RECT  0.084 24.432 0.601 24.456 ;
     RECT  0.06 24.456 0.601 24.528 ;
     RECT  0.084 24.528 0.601 24.552 ;
     RECT  0.06 24.552 0.601 24.624 ;
     RECT  0.084 24.624 0.601 24.648 ;
     RECT  0.06 24.648 0.601 24.72 ;
     RECT  0.084 24.72 0.601 24.744 ;
     RECT  0.06 24.744 0.601 24.816 ;
     RECT  0.084 24.816 0.601 24.84 ;
     RECT  0.06 24.84 0.601 24.912 ;
     RECT  0.084 24.912 0.601 24.936 ;
     RECT  0.06 24.936 0.601 25.008 ;
     RECT  0.084 25.008 0.601 25.032 ;
     RECT  0.06 25.032 0.601 25.104 ;
     RECT  0.084 25.104 0.601 25.128 ;
     RECT  0.06 25.128 0.601 25.2 ;
     RECT  0.084 25.2 0.601 25.224 ;
     RECT  0.06 25.224 0.601 25.296 ;
     RECT  0.084 25.296 0.601 25.32 ;
     RECT  0.06 25.32 0.601 25.392 ;
     RECT  0.084 25.392 0.601 25.416 ;
     RECT  0.06 25.416 0.601 25.488 ;
     RECT  0.084 25.488 0.601 25.512 ;
     RECT  0.06 25.512 0.601 25.584 ;
     RECT  0.084 25.584 0.601 25.608 ;
     RECT  0.06 25.608 0.601 25.68 ;
     RECT  0.084 25.68 0.601 25.704 ;
     RECT  0.06 25.704 0.601 25.776 ;
     RECT  0.084 25.776 0.601 25.8 ;
     RECT  0.06 25.8 0.601 25.872 ;
     RECT  0.084 25.872 0.601 25.896 ;
     RECT  0.06 25.896 0.601 25.968 ;
     RECT  0.084 25.968 0.601 25.992 ;
     RECT  0.06 25.992 0.601 26.064 ;
     RECT  0.084 26.064 0.601 26.088 ;
     RECT  0.06 26.088 0.601 26.16 ;
     RECT  0.084 26.16 0.601 26.184 ;
     RECT  0.06 26.184 0.601 26.256 ;
     RECT  0.084 26.256 0.601 26.28 ;
     RECT  0.06 26.28 0.601 26.352 ;
     RECT  0.084 26.352 0.601 26.376 ;
     RECT  0.06 26.376 0.601 26.448 ;
     RECT  0.084 26.448 0.601 26.472 ;
     RECT  0.06 26.472 0.601 26.544 ;
     RECT  0.084 26.544 0.601 26.568 ;
     RECT  0.06 26.568 0.601 26.64 ;
     RECT  0.084 26.64 0.601 26.664 ;
     RECT  0.06 26.664 0.601 26.736 ;
     RECT  0.084 26.736 0.601 26.76 ;
     RECT  0.06 26.76 0.601 26.832 ;
     RECT  0.084 26.832 0.601 26.856 ;
     RECT  0.06 26.856 0.601 26.928 ;
     RECT  0.084 26.928 0.601 26.952 ;
     RECT  0.06 26.952 0.601 27.024 ;
     RECT  0.084 27.024 0.601 27.048 ;
     RECT  0.06 27.048 0.601 27.12 ;
     RECT  0.084 27.12 0.601 27.144 ;
     RECT  0.06 27.144 0.601 27.216 ;
     RECT  0.084 27.216 0.601 27.24 ;
     RECT  0.06 27.24 0.601 27.312 ;
     RECT  0.084 27.312 0.601 27.336 ;
     RECT  0.06 27.336 0.601 27.408 ;
     RECT  0.084 27.408 0.601 27.432 ;
     RECT  0.06 27.432 0.601 27.504 ;
     RECT  0.084 27.504 0.601 27.528 ;
     RECT  0.06 27.528 0.601 27.6 ;
     RECT  0.084 27.6 0.601 27.624 ;
     RECT  0.06 27.624 0.601 27.696 ;
     RECT  0.084 27.696 0.601 27.72 ;
     RECT  0.06 27.72 0.601 27.792 ;
     RECT  0.084 27.792 0.601 27.816 ;
     RECT  0.06 27.816 0.601 27.888 ;
     RECT  0.084 27.888 0.601 27.912 ;
     RECT  0.06 27.912 0.601 27.984 ;
     RECT  0.084 27.984 0.601 28.008 ;
     RECT  0.06 28.008 0.601 28.08 ;
     RECT  0.084 28.08 0.601 28.104 ;
     RECT  0.06 28.104 0.601 28.176 ;
     RECT  0.084 28.176 0.601 28.2 ;
     RECT  0.06 28.2 0.601 28.272 ;
     RECT  0.084 28.272 0.601 28.296 ;
     RECT  0.06 28.296 0.601 28.368 ;
     RECT  0.084 28.368 0.601 28.392 ;
     RECT  0.06 28.392 0.601 28.464 ;
     RECT  0.084 28.464 0.601 28.488 ;
     RECT  0.06 28.488 0.601 28.56 ;
     RECT  0.084 28.56 0.601 28.584 ;
     RECT  0.06 28.584 0.601 28.656 ;
     RECT  0.084 28.656 0.601 28.68 ;
     RECT  0.06 28.68 0.601 28.752 ;
     RECT  0.084 28.752 0.601 28.776 ;
     RECT  0.06 28.776 0.601 28.848 ;
     RECT  0.084 28.848 0.601 28.872 ;
     RECT  0.06 28.872 0.601 28.944 ;
     RECT  0.084 28.944 0.601 28.968 ;
     RECT  0.06 28.968 0.601 29.04 ;
     RECT  0.084 29.04 0.601 29.064 ;
     RECT  0.06 29.064 0.601 29.136 ;
     RECT  0.084 29.136 0.601 29.16 ;
     RECT  0.06 29.16 0.601 29.232 ;
     RECT  0.084 29.232 0.601 29.256 ;
     RECT  0.06 29.256 0.601 29.328 ;
     RECT  0.084 29.328 0.601 29.352 ;
     RECT  0.06 29.352 0.601 29.424 ;
     RECT  0.084 29.424 0.601 29.448 ;
     RECT  0.06 29.448 0.601 29.52 ;
     RECT  0.084 29.52 0.601 29.544 ;
     RECT  0.06 29.544 0.601 29.616 ;
     RECT  0.084 29.616 0.601 29.64 ;
     RECT  0.06 29.64 0.601 29.712 ;
     RECT  0.084 29.712 0.601 29.736 ;
     RECT  0.06 29.736 0.601 29.808 ;
     RECT  0.084 29.808 0.601 29.832 ;
     RECT  0.06 29.832 0.601 29.904 ;
     RECT  0.084 29.904 0.601 29.928 ;
     RECT  0.06 29.928 0.601 30 ;
     RECT  0.084 30 0.601 30.024 ;
     RECT  0.06 30.024 0.601 30.096 ;
     RECT  0.084 30.096 0.601 30.12 ;
     RECT  0.06 30.12 0.601 30.192 ;
     RECT  0.084 30.192 0.601 30.216 ;
     RECT  0.06 30.216 0.601 30.288 ;
     RECT  0.084 30.288 0.601 30.312 ;
     RECT  0.06 30.312 0.601 30.384 ;
     RECT  0.084 30.384 0.601 30.408 ;
     RECT  0.06 30.408 0.601 30.48 ;
     RECT  0.084 30.48 0.601 30.504 ;
     RECT  0.06 30.504 0.601 30.576 ;
     RECT  0.084 30.576 0.601 30.6 ;
     RECT  0.06 30.6 0.601 30.672 ;
     RECT  0.084 30.672 0.601 30.696 ;
     RECT  0.06 30.696 0.601 30.768 ;
     RECT  0.084 30.768 0.601 30.792 ;
     RECT  0.06 30.792 0.601 30.864 ;
     RECT  0.084 30.864 0.601 30.888 ;
     RECT  0.06 30.888 0.601 30.96 ;
     RECT  0.084 30.96 0.601 30.984 ;
     RECT  0.06 30.984 0.601 31.056 ;
     RECT  0.084 31.056 0.601 31.08 ;
     RECT  0.06 31.08 0.601 31.152 ;
     RECT  0.084 31.152 0.601 31.176 ;
     RECT  0.06 31.176 0.601 31.248 ;
     RECT  0.084 31.248 0.601 31.272 ;
     RECT  0.06 31.272 0.601 31.344 ;
     RECT  0.084 31.344 0.601 31.368 ;
     RECT  0.06 31.368 0.601 31.44 ;
     RECT  0.084 31.44 0.601 31.464 ;
     RECT  0.06 31.464 0.601 31.536 ;
     RECT  0.084 31.536 0.601 31.56 ;
     RECT  0.06 31.56 0.601 31.632 ;
     RECT  0.084 31.632 0.601 31.656 ;
     RECT  0.06 31.656 0.601 31.728 ;
     RECT  0.084 31.728 0.601 31.752 ;
     RECT  0.06 31.752 0.601 31.824 ;
     RECT  0.084 31.824 0.601 31.848 ;
     RECT  0.06 31.848 0.601 31.92 ;
     RECT  0.084 31.92 0.601 31.944 ;
     RECT  0.06 31.944 0.601 32.016 ;
     RECT  0.084 32.016 0.601 32.04 ;
     RECT  0.06 32.04 0.601 32.112 ;
     RECT  0.084 32.112 0.601 32.136 ;
     RECT  0.06 32.136 0.601 32.208 ;
     RECT  0.084 32.208 0.601 32.232 ;
     RECT  0.06 32.232 0.601 32.304 ;
     RECT  0.084 32.304 0.601 32.328 ;
     RECT  0.06 32.328 0.601 32.4 ;
     RECT  0.084 32.4 0.601 32.424 ;
     RECT  0.06 32.424 0.601 32.496 ;
     RECT  0.084 32.496 0.601 32.52 ;
     RECT  0.06 32.52 0.601 32.592 ;
     RECT  0.084 32.592 0.601 32.616 ;
     RECT  0.06 32.616 0.601 32.688 ;
     RECT  0.084 32.688 0.601 32.712 ;
     RECT  0.06 32.712 0.601 32.784 ;
     RECT  0.084 32.784 0.601 32.808 ;
     RECT  0.06 32.808 0.601 32.88 ;
     RECT  0.084 32.88 0.601 32.904 ;
     RECT  0.06 32.904 0.601 32.976 ;
     RECT  0.084 32.976 0.601 33 ;
     RECT  0.06 33 0.601 33.072 ;
     RECT  0.084 33.072 0.601 33.096 ;
     RECT  0.06 33.096 0.601 33.168 ;
     RECT  0.084 33.168 0.601 33.192 ;
     RECT  0.06 33.192 0.601 33.264 ;
     RECT  0.084 33.264 0.601 33.288 ;
     RECT  0.06 33.288 0.601 33.36 ;
     RECT  0.084 33.36 0.601 33.384 ;
     RECT  0.06 33.384 0.601 33.456 ;
     RECT  0.084 33.456 0.601 33.48 ;
     RECT  0.06 33.48 0.601 33.552 ;
     RECT  0.084 33.552 0.601 33.576 ;
     RECT  0.06 33.576 0.601 33.648 ;
     RECT  0.084 33.648 0.601 33.672 ;
     RECT  0.06 33.672 0.601 33.744 ;
     RECT  0.084 33.744 0.601 33.768 ;
     RECT  0.06 33.768 0.601 33.84 ;
     RECT  0.084 33.84 0.601 33.864 ;
     RECT  0.06 33.864 0.601 33.936 ;
     RECT  0.084 33.936 0.601 33.96 ;
     RECT  0.06 33.96 0.601 34.032 ;
     RECT  0.084 34.032 0.601 34.056 ;
     RECT  0.06 34.056 0.601 34.896 ;
     RECT  0.084 34.896 0.601 34.92 ;
     RECT  0.06 34.92 0.601 34.992 ;
     RECT  0.084 34.992 0.601 35.016 ;
     RECT  0.06 35.016 0.601 35.088 ;
     RECT  0.084 35.088 0.601 35.112 ;
     RECT  0.06 35.112 0.601 35.184 ;
     RECT  0.084 35.184 0.601 35.208 ;
     RECT  0.06 35.208 0.601 35.28 ;
     RECT  0.084 35.28 0.601 35.304 ;
     RECT  0.06 35.304 0.601 35.376 ;
     RECT  0.084 35.376 0.601 35.4 ;
     RECT  0.06 35.4 0.601 35.472 ;
     RECT  0.084 35.472 0.601 35.496 ;
     RECT  0.06 35.496 0.601 35.568 ;
     RECT  0.084 35.568 0.601 35.592 ;
     RECT  0.06 35.592 0.601 35.664 ;
     RECT  0.084 35.664 0.601 35.688 ;
     RECT  0.06 35.688 0.601 35.76 ;
     RECT  0.084 35.76 0.601 35.784 ;
     RECT  0.06 35.784 0.601 35.856 ;
     RECT  0.084 35.856 0.601 35.88 ;
     RECT  0.06 35.88 0.601 35.952 ;
     RECT  0.084 35.952 0.601 35.976 ;
     RECT  0.06 35.976 0.601 36.048 ;
     RECT  0.084 36.048 0.601 36.072 ;
     RECT  0.06 36.072 0.601 36.144 ;
     RECT  0.084 36.144 0.601 36.168 ;
     RECT  0.06 36.168 0.601 36.24 ;
     RECT  0.084 36.24 0.601 36.264 ;
     RECT  0.06 36.264 0.601 36.336 ;
     RECT  0.084 36.336 0.601 36.36 ;
     RECT  0.06 36.36 0.601 36.432 ;
     RECT  0.084 36.432 0.601 36.456 ;
     RECT  0.06 36.456 0.601 36.528 ;
     RECT  0.084 36.528 0.601 36.552 ;
     RECT  0.06 36.552 0.601 36.624 ;
     RECT  0.084 36.624 0.601 36.648 ;
     RECT  0.06 36.648 0.601 36.72 ;
     RECT  0.084 36.72 0.601 36.744 ;
     RECT  0.06 36.744 0.601 36.816 ;
     RECT  0.084 36.816 0.601 36.84 ;
     RECT  0.06 36.84 0.601 36.912 ;
     RECT  0.084 36.912 0.601 36.936 ;
     RECT  0.06 36.936 0.601 37.008 ;
     RECT  0.084 37.008 0.601 37.032 ;
     RECT  0.06 37.032 0.601 37.104 ;
     RECT  0.084 37.104 0.601 37.128 ;
     RECT  0.06 37.128 0.601 37.2 ;
     RECT  0.084 37.2 0.601 37.224 ;
     RECT  0.06 37.224 0.601 37.296 ;
     RECT  0.084 37.296 0.601 37.32 ;
     RECT  0.06 37.32 0.601 37.392 ;
     RECT  0.084 37.392 0.601 37.416 ;
     RECT  0.06 37.416 0.601 37.488 ;
     RECT  0.084 37.488 0.601 37.512 ;
     RECT  0.06 37.512 0.601 37.584 ;
     RECT  0.084 37.584 0.601 37.608 ;
     RECT  0.06 37.608 0.601 37.68 ;
     RECT  0.084 37.68 0.601 37.704 ;
     RECT  0.06 37.704 0.601 37.776 ;
     RECT  0.084 37.776 0.601 37.8 ;
     RECT  0.06 37.8 0.601 37.872 ;
     RECT  0.084 37.872 0.601 37.896 ;
     RECT  0.06 37.896 0.601 37.968 ;
     RECT  0.084 37.968 0.601 37.992 ;
     RECT  0.06 37.992 0.601 38.064 ;
     RECT  0.084 38.064 0.601 38.088 ;
     RECT  0.06 38.088 0.601 38.16 ;
     RECT  0.084 38.16 0.601 38.184 ;
     RECT  0.06 38.184 0.601 38.256 ;
     RECT  0.084 38.256 0.601 38.28 ;
     RECT  0.06 38.28 0.601 38.352 ;
     RECT  0.084 38.352 0.601 38.376 ;
     RECT  0.06 38.376 0.601 38.448 ;
     RECT  0.084 38.448 0.601 38.472 ;
     RECT  0.06 38.472 0.601 38.544 ;
     RECT  0.084 38.544 0.601 38.568 ;
     RECT  0.06 38.568 0.601 38.64 ;
     RECT  0.084 38.64 0.601 38.664 ;
     RECT  0.06 38.664 0.601 38.736 ;
     RECT  0.084 38.736 0.601 38.76 ;
     RECT  0.06 38.76 0.601 38.832 ;
     RECT  0.084 38.832 0.601 38.856 ;
     RECT  0.06 38.856 0.601 38.928 ;
     RECT  0.084 38.928 0.601 38.952 ;
     RECT  0.06 38.952 0.601 39.024 ;
     RECT  0.084 39.024 0.601 39.048 ;
     RECT  0.06 39.048 0.601 39.12 ;
     RECT  0.084 39.12 0.601 39.144 ;
     RECT  0.06 39.144 0.601 39.216 ;
     RECT  0.084 39.216 0.601 39.24 ;
     RECT  0.06 39.24 0.601 39.312 ;
     RECT  0.084 39.312 0.601 39.336 ;
     RECT  0.06 39.336 0.601 39.408 ;
     RECT  0.084 39.408 0.601 39.432 ;
     RECT  0.06 39.432 0.601 39.504 ;
     RECT  0.084 39.504 0.601 39.528 ;
     RECT  0.06 39.528 0.601 39.6 ;
     RECT  0.084 39.6 0.601 39.624 ;
     RECT  0.06 39.624 0.601 39.696 ;
     RECT  0.084 39.696 0.601 39.72 ;
     RECT  0.06 39.72 0.601 39.792 ;
     RECT  0.084 39.792 0.601 39.816 ;
     RECT  0.06 39.816 0.601 39.888 ;
     RECT  0.084 39.888 0.601 39.912 ;
     RECT  0.06 39.912 0.601 39.984 ;
     RECT  0.084 39.984 0.601 40.008 ;
     RECT  0.06 40.008 0.601 40.08 ;
     RECT  0.084 40.08 0.601 40.104 ;
     RECT  0.06 40.104 0.601 40.176 ;
     RECT  0.084 40.176 0.601 40.2 ;
     RECT  0.06 40.2 0.601 40.272 ;
     RECT  0.084 40.272 0.601 40.296 ;
     RECT  0.06 40.296 0.601 40.368 ;
     RECT  0.084 40.368 0.601 40.392 ;
     RECT  0.06 40.392 0.601 40.464 ;
     RECT  0.084 40.464 0.601 40.488 ;
     RECT  0.06 40.488 0.601 40.56 ;
     RECT  0.084 40.56 0.601 40.584 ;
     RECT  0.06 40.584 0.601 40.656 ;
     RECT  0.084 40.656 0.601 40.68 ;
     RECT  0.06 40.68 0.601 40.752 ;
     RECT  0.084 40.752 0.601 40.776 ;
     RECT  0.06 40.776 0.601 40.848 ;
     RECT  0.084 40.848 0.601 40.872 ;
     RECT  0.06 40.872 0.601 40.944 ;
     RECT  0.084 40.944 0.601 40.968 ;
     RECT  0.241 42.144 0.601 44.04 ;
     RECT  0.601 15.696 1.109 44.04 ;
     RECT  1.109 15.696 2.197 37.416 ;
     RECT  1.109 38.448 2.197 44.04 ;
     RECT  2.197 15.696 2.408 44.04 ;
     RECT  2.408 2.148 2.512 51.852 ;
     RECT  2.512 2.418 2.704 51.582 ;
     RECT  2.704 15.792 2.765 16.392 ;
     RECT  2.704 18.144 2.765 34.104 ;
     RECT  2.704 35.472 2.765 43.32 ;
     RECT  2.765 18.192 2.801 34.104 ;
     RECT  2.765 16.272 2.837 16.392 ;
     RECT  2.765 35.52 2.837 43.32 ;
     RECT  2.837 40.08 2.873 40.152 ;
     RECT  2.837 35.52 2.963 38.808 ;
     RECT  2.801 18.192 3.089 33.624 ;
     RECT  2.837 41.472 3.125 43.32 ;
     RECT  2.963 38.784 3.155 38.808 ;
     RECT  3.089 18.192 3.161 33.576 ;
     RECT  3.161 25.536 3.197 33.576 ;
     RECT  3.161 18.192 3.233 24.504 ;
     RECT  3.125 42.48 3.251 43.32 ;
     RECT  2.837 16.32 3.269 16.392 ;
     RECT  3.197 27.888 3.277 33.576 ;
     RECT  3.277 28.512 3.305 33.576 ;
     RECT  2.873 40.08 3.347 40.104 ;
     RECT  3.305 28.704 3.377 33.576 ;
     RECT  3.377 30.768 3.385 33.576 ;
     RECT  3.233 18.192 3.413 18.984 ;
     RECT  3.233 20.16 3.413 24.504 ;
     RECT  3.413 20.16 3.449 21.816 ;
     RECT  3.385 31.104 3.449 33.576 ;
     RECT  2.963 35.76 3.557 37.128 ;
     RECT  3.449 31.104 3.629 33.384 ;
     RECT  3.125 41.472 3.683 41.496 ;
     RECT  3.449 20.16 3.701 21.672 ;
     RECT  3.197 25.536 3.709 26.76 ;
     RECT  3.413 23.232 3.737 24.504 ;
     RECT  3.629 31.104 3.737 33.288 ;
     RECT  3.251 43.008 3.779 43.32 ;
     RECT  3.701 20.304 3.817 21.672 ;
     RECT  3.817 20.304 3.917 21.192 ;
     RECT  3.557 36 3.917 37.128 ;
     RECT  3.737 23.232 3.953 24.216 ;
     RECT  3.737 31.152 3.953 33.048 ;
     RECT  3.953 31.2 3.971 33.048 ;
     RECT  3.917 21.168 3.989 21.192 ;
     RECT  3.953 23.232 3.989 24.12 ;
     RECT  3.917 36 3.989 36.648 ;
     RECT  3.709 25.536 3.997 26.232 ;
     RECT  3.377 28.704 4.025 29.784 ;
     RECT  3.971 31.2 4.061 32.52 ;
     RECT  3.989 36.624 4.061 36.648 ;
     RECT  4.061 31.2 4.097 32.088 ;
     RECT  4.097 31.2 4.993 31.8 ;
     RECT  3.269 16.32 5.108 16.344 ;
     RECT  3.413 18.192 5.108 18.216 ;
     RECT  3.989 23.568 5.108 24.12 ;
     RECT  3.997 25.536 5.108 25.56 ;
     RECT  4.025 28.992 5.108 29.784 ;
     RECT  4.993 31.152 5.108 31.8 ;
     RECT  3.779 43.008 5.108 43.032 ;
     RECT  5.108 2.148 5.212 51.852 ;
     RECT  5.212 2.418 5.404 51.582 ;
     RECT  5.404 29.76 5.933 29.784 ;
     RECT  5.404 23.28 6.041 24.12 ;
     RECT  6.041 23.28 6.581 23.928 ;
     RECT  5.404 31.152 6.685 31.8 ;
     RECT  6.685 31.152 6.797 31.944 ;
     RECT  6.581 23.904 7.808 23.928 ;
     RECT  6.797 31.152 7.808 31.416 ;
     RECT  5.404 43.008 7.808 43.032 ;
     RECT  7.808 2.148 7.912 51.852 ;
     RECT  7.912 2.418 8.104 51.582 ;
     RECT  8.104 31.152 8.741 31.416 ;
     RECT  8.741 31.2 10.309 31.416 ;
     RECT  10.309 20.688 10.508 20.712 ;
     RECT  8.104 23.904 10.508 23.928 ;
     RECT  10.309 31.2 10.508 31.512 ;
     RECT  10.357 35.856 10.508 35.88 ;
     RECT  8.104 43.008 10.508 43.032 ;
     RECT  10.508 2.148 10.612 51.852 ;
     RECT  10.612 2.418 10.804 51.582 ;
     RECT  10.804 31.2 12.085 31.512 ;
     RECT  10.804 35.712 12.089 36.024 ;
     RECT  11.977 28.944 12.133 28.968 ;
     RECT  12.092 27.84 12.179 27.864 ;
     RECT  10.804 20.688 12.265 20.712 ;
     RECT  10.804 23.904 12.301 23.928 ;
     RECT  12.133 28.944 12.301 29.064 ;
     RECT  12.085 30.864 12.337 31.512 ;
     RECT  12.089 35.712 12.373 35.832 ;
     RECT  12.301 28.8 12.409 29.064 ;
     RECT  12.265 20.688 12.517 20.808 ;
     RECT  12.373 35.328 12.661 35.832 ;
     RECT  12.301 23.376 12.949 23.928 ;
     RECT  12.697 25.152 12.949 25.176 ;
     RECT  12.013 26.208 13.021 26.76 ;
     RECT  12.62 33.84 13.021 33.864 ;
     RECT  12.949 23.376 13.057 25.176 ;
     RECT  13.021 26.208 13.057 27.336 ;
     RECT  12.409 28.8 13.093 29.496 ;
     RECT  12.337 30.864 13.093 32.328 ;
     RECT  13.021 33.6 13.093 33.864 ;
     RECT  12.661 34.896 13.093 35.832 ;
     RECT  12.517 20.4 13.208 20.808 ;
     RECT  13.057 23.376 13.208 27.336 ;
     RECT  13.093 28.8 13.208 29.784 ;
     RECT  13.093 30.864 13.208 35.832 ;
     RECT  13.208 2.148 13.312 51.852 ;
     RECT  13.312 2.418 13.504 51.582 ;
     RECT  13.504 33.6 13.997 35.832 ;
     RECT  13.997 35.808 14.291 35.832 ;
     RECT  13.997 33.6 14.393 34.776 ;
     RECT  13.504 23.232 14.569 24.648 ;
     RECT  13.504 25.728 14.569 26.76 ;
     RECT  14.569 23.232 14.641 26.76 ;
     RECT  13.504 28.512 14.641 30.168 ;
     RECT  13.504 31.2 14.641 32.328 ;
     RECT  13.504 20.4 14.785 20.712 ;
     RECT  14.641 23.232 14.785 26.808 ;
     RECT  14.641 28.512 14.789 32.328 ;
     RECT  14.785 22.944 14.857 26.808 ;
     RECT  14.857 22.944 15.289 27.336 ;
     RECT  14.785 20.208 15.349 20.712 ;
     RECT  14.789 28.848 15.397 32.328 ;
     RECT  15.289 22.944 15.433 27.384 ;
     RECT  14.393 34.368 15.757 34.776 ;
     RECT  15.397 28.848 15.793 32.808 ;
     RECT  15.757 33.936 15.865 34.776 ;
     RECT  15.349 20.208 15.908 21 ;
     RECT  15.433 22.944 15.908 27.48 ;
     RECT  15.793 28.512 15.908 32.808 ;
     RECT  15.865 33.936 15.908 35.256 ;
     RECT  15.908 2.148 16.012 51.852 ;
     RECT  16.012 2.418 16.204 51.582 ;
     RECT  16.204 23.136 16.625 28.536 ;
     RECT  16.204 30.096 17.021 35.256 ;
     RECT  16.625 23.136 17.129 23.928 ;
     RECT  17.021 30.096 17.201 34.92 ;
     RECT  16.625 24.912 17.489 28.536 ;
     RECT  17.129 23.136 17.597 23.16 ;
     RECT  17.201 30.096 18.241 34.824 ;
     RECT  16.204 20.592 18.608 20.712 ;
     RECT  18.493 22.848 18.608 22.872 ;
     RECT  17.489 25.536 18.608 28.536 ;
     RECT  18.241 30.096 18.608 34.92 ;
     RECT  18.608 2.148 18.712 51.852 ;
     RECT  18.712 2.418 18.904 51.582 ;
     RECT  18.904 23.472 19.897 35.112 ;
     RECT  18.904 20.112 20.185 20.712 ;
     RECT  19.897 23.376 20.401 35.208 ;
     RECT  20.185 20.112 21.445 20.808 ;
     RECT  21.445 20.016 21.481 20.808 ;
     RECT  21.481 19.92 21.516 19.944 ;
     RECT  21.481 19.944 21.564 20.016 ;
     RECT  21.481 20.016 21.516 20.04 ;
     RECT  21.481 20.04 21.564 20.112 ;
     RECT  21.481 20.112 21.516 20.136 ;
     RECT  21.481 20.136 21.564 20.208 ;
     RECT  21.481 20.208 21.516 20.232 ;
     RECT  21.481 20.232 21.564 20.304 ;
     RECT  21.481 20.304 21.516 20.328 ;
     RECT  21.481 20.328 21.564 20.4 ;
     RECT  21.481 20.4 21.516 20.424 ;
     RECT  21.481 20.424 21.564 20.496 ;
     RECT  21.481 20.496 21.516 20.52 ;
     RECT  21.481 20.52 21.564 20.592 ;
     RECT  21.481 20.592 21.516 20.616 ;
     RECT  21.481 20.616 21.564 20.688 ;
     RECT  21.481 20.688 21.516 20.712 ;
     RECT  21.481 20.712 21.564 20.784 ;
     RECT  21.481 20.784 21.516 20.808 ;
     RECT  20.401 22.992 21.516 23.016 ;
     RECT  20.401 23.016 21.564 23.088 ;
     RECT  20.401 23.088 21.516 23.112 ;
     RECT  20.401 23.112 21.564 23.184 ;
     RECT  20.401 23.184 21.516 23.208 ;
     RECT  20.401 23.208 21.564 23.28 ;
     RECT  20.401 23.28 21.516 23.304 ;
     RECT  20.401 23.304 21.564 23.376 ;
     RECT  20.401 23.376 21.516 23.4 ;
     RECT  20.401 23.4 21.564 23.472 ;
     RECT  20.401 23.472 21.516 23.496 ;
     RECT  20.401 23.496 21.564 23.568 ;
     RECT  20.401 23.568 21.516 23.592 ;
     RECT  20.401 23.592 21.564 23.664 ;
     RECT  20.401 23.664 21.516 23.688 ;
     RECT  20.401 23.688 21.564 23.76 ;
     RECT  20.401 23.76 21.516 23.784 ;
     RECT  20.401 23.784 21.564 23.856 ;
     RECT  20.401 23.856 21.516 23.88 ;
     RECT  20.401 23.88 21.564 23.952 ;
     RECT  20.401 23.952 21.516 23.976 ;
     RECT  20.401 23.976 21.564 24.048 ;
     RECT  20.401 24.048 21.516 24.072 ;
     RECT  20.401 24.072 21.564 24.144 ;
     RECT  20.401 24.144 21.516 24.168 ;
     RECT  20.401 24.168 21.564 24.24 ;
     RECT  20.401 24.24 21.516 24.264 ;
     RECT  20.401 24.264 21.564 24.336 ;
     RECT  20.401 24.336 21.516 24.36 ;
     RECT  20.401 24.36 21.564 24.432 ;
     RECT  20.401 24.432 21.516 24.456 ;
     RECT  20.401 24.456 21.564 24.528 ;
     RECT  20.401 24.528 21.516 24.552 ;
     RECT  20.401 24.552 21.564 24.624 ;
     RECT  20.401 24.624 21.516 24.648 ;
     RECT  20.401 24.648 21.564 24.72 ;
     RECT  20.401 24.72 21.516 24.744 ;
     RECT  20.401 24.744 21.564 24.816 ;
     RECT  20.401 24.816 21.516 24.84 ;
     RECT  20.401 24.84 21.564 24.912 ;
     RECT  20.401 24.912 21.516 24.936 ;
     RECT  20.401 24.936 21.564 25.008 ;
     RECT  20.401 25.008 21.516 25.032 ;
     RECT  20.401 25.032 21.564 25.104 ;
     RECT  20.401 25.104 21.516 25.128 ;
     RECT  20.401 25.128 21.564 25.2 ;
     RECT  20.401 25.2 21.516 25.224 ;
     RECT  20.401 25.224 21.564 25.296 ;
     RECT  20.401 25.296 21.516 25.32 ;
     RECT  20.401 25.32 21.564 25.392 ;
     RECT  20.401 25.392 21.516 25.416 ;
     RECT  20.401 25.416 21.564 25.488 ;
     RECT  20.401 25.488 21.516 25.512 ;
     RECT  20.401 25.512 21.564 25.584 ;
     RECT  20.401 25.584 21.516 25.608 ;
     RECT  20.401 25.608 21.564 25.68 ;
     RECT  20.401 25.68 21.516 25.704 ;
     RECT  20.401 25.704 21.564 25.776 ;
     RECT  20.401 25.776 21.516 25.8 ;
     RECT  20.401 25.8 21.564 25.872 ;
     RECT  20.401 25.872 21.516 25.896 ;
     RECT  20.401 25.896 21.564 25.968 ;
     RECT  20.401 25.968 21.516 25.992 ;
     RECT  20.401 25.992 21.564 26.064 ;
     RECT  20.401 26.064 21.516 26.088 ;
     RECT  20.401 26.088 21.564 26.16 ;
     RECT  20.401 26.16 21.516 26.184 ;
     RECT  20.401 26.184 21.564 26.256 ;
     RECT  20.401 26.256 21.516 26.28 ;
     RECT  20.401 26.28 21.564 26.352 ;
     RECT  20.401 26.352 21.516 26.376 ;
     RECT  20.401 26.376 21.564 26.448 ;
     RECT  20.401 26.448 21.516 26.472 ;
     RECT  20.401 26.472 21.564 26.544 ;
     RECT  20.401 26.544 21.516 26.568 ;
     RECT  20.401 26.568 21.564 26.64 ;
     RECT  20.401 26.64 21.516 26.664 ;
     RECT  20.401 26.664 21.564 26.736 ;
     RECT  20.401 26.736 21.516 26.76 ;
     RECT  20.401 26.76 21.564 26.832 ;
     RECT  20.401 26.832 21.516 26.856 ;
     RECT  20.401 26.856 21.564 26.928 ;
     RECT  20.401 26.928 21.516 26.952 ;
     RECT  20.401 26.952 21.564 27.024 ;
     RECT  20.401 27.024 21.516 27.048 ;
     RECT  20.401 27.048 21.564 27.12 ;
     RECT  20.401 27.12 21.516 27.144 ;
     RECT  20.401 27.144 21.564 27.216 ;
     RECT  20.401 27.216 21.516 27.24 ;
     RECT  20.401 27.24 21.564 27.312 ;
     RECT  20.401 27.312 21.516 27.336 ;
     RECT  20.401 27.336 21.564 27.408 ;
     RECT  20.401 27.408 21.516 27.432 ;
     RECT  20.401 27.432 21.564 27.504 ;
     RECT  20.401 27.504 21.516 27.528 ;
     RECT  20.401 27.528 21.564 27.6 ;
     RECT  20.401 27.6 21.516 27.624 ;
     RECT  20.401 27.624 21.564 27.696 ;
     RECT  20.401 27.696 21.516 27.72 ;
     RECT  20.401 27.72 21.564 27.792 ;
     RECT  20.401 27.792 21.516 27.816 ;
     RECT  20.401 27.816 21.564 27.888 ;
     RECT  20.401 27.888 21.516 27.912 ;
     RECT  20.401 27.912 21.564 27.984 ;
     RECT  20.401 27.984 21.516 28.008 ;
     RECT  20.401 28.008 21.564 28.08 ;
     RECT  20.401 28.08 21.516 28.104 ;
     RECT  20.401 28.104 21.564 28.176 ;
     RECT  20.401 28.176 21.516 28.2 ;
     RECT  20.401 28.2 21.564 28.272 ;
     RECT  20.401 28.272 21.516 28.296 ;
     RECT  20.401 28.296 21.564 28.368 ;
     RECT  20.401 28.368 21.516 28.392 ;
     RECT  20.401 28.392 21.564 28.464 ;
     RECT  20.401 28.464 21.516 28.488 ;
     RECT  20.401 28.488 21.564 28.56 ;
     RECT  20.401 28.56 21.516 28.584 ;
     RECT  20.401 28.584 21.564 28.656 ;
     RECT  20.401 28.656 21.516 28.68 ;
     RECT  20.401 28.68 21.564 28.752 ;
     RECT  20.401 28.752 21.516 28.776 ;
     RECT  20.401 28.776 21.564 28.848 ;
     RECT  20.401 28.848 21.516 28.872 ;
     RECT  20.401 28.872 21.564 28.944 ;
     RECT  20.401 28.944 21.516 28.968 ;
     RECT  20.401 28.968 21.564 29.04 ;
     RECT  20.401 29.04 21.516 29.064 ;
     RECT  20.401 29.064 21.564 29.136 ;
     RECT  20.401 29.136 21.516 29.16 ;
     RECT  20.401 29.16 21.564 29.232 ;
     RECT  20.401 29.232 21.516 29.256 ;
     RECT  20.401 29.256 21.564 29.328 ;
     RECT  20.401 29.328 21.516 29.352 ;
     RECT  20.401 29.352 21.564 29.424 ;
     RECT  20.401 29.424 21.516 29.448 ;
     RECT  20.401 29.448 21.564 29.52 ;
     RECT  20.401 29.52 21.516 29.544 ;
     RECT  20.401 29.544 21.564 29.616 ;
     RECT  20.401 29.616 21.516 29.64 ;
     RECT  20.401 29.64 21.564 29.712 ;
     RECT  20.401 29.712 21.516 29.736 ;
     RECT  20.401 29.736 21.564 29.808 ;
     RECT  20.401 29.808 21.516 29.832 ;
     RECT  20.401 29.832 21.564 29.904 ;
     RECT  20.401 29.904 21.516 29.928 ;
     RECT  20.401 29.928 21.564 30 ;
     RECT  20.401 30 21.516 30.024 ;
     RECT  20.401 30.024 21.564 30.096 ;
     RECT  20.401 30.096 21.516 30.12 ;
     RECT  20.401 30.12 21.564 30.192 ;
     RECT  20.401 30.192 21.516 30.216 ;
     RECT  20.401 30.216 21.564 30.288 ;
     RECT  20.401 30.288 21.516 30.312 ;
     RECT  20.401 30.312 21.564 30.384 ;
     RECT  20.401 30.384 21.516 30.408 ;
     RECT  20.401 30.408 21.564 30.48 ;
     RECT  20.401 30.48 21.516 30.504 ;
     RECT  20.401 30.504 21.564 30.576 ;
     RECT  20.401 30.576 21.516 30.6 ;
     RECT  20.401 30.6 21.564 30.672 ;
     RECT  20.401 30.672 21.516 30.696 ;
     RECT  20.401 30.696 21.564 30.768 ;
     RECT  20.401 30.768 21.516 30.792 ;
     RECT  20.401 30.792 21.564 30.864 ;
     RECT  20.401 30.864 21.516 30.888 ;
     RECT  20.401 30.888 21.564 30.96 ;
     RECT  20.401 30.96 21.516 30.984 ;
     RECT  20.401 30.984 21.564 31.056 ;
     RECT  20.401 31.056 21.516 31.08 ;
     RECT  20.401 31.08 21.564 31.152 ;
     RECT  20.401 31.152 21.516 31.176 ;
     RECT  20.401 31.176 21.564 31.248 ;
     RECT  20.401 31.248 21.516 31.272 ;
     RECT  20.401 31.272 21.564 31.344 ;
     RECT  20.401 31.344 21.516 31.368 ;
     RECT  20.401 31.368 21.564 31.44 ;
     RECT  20.401 31.44 21.516 31.464 ;
     RECT  20.401 31.464 21.564 31.536 ;
     RECT  20.401 31.536 21.516 31.56 ;
     RECT  20.401 31.56 21.564 31.632 ;
     RECT  20.401 31.632 21.516 31.656 ;
     RECT  20.401 31.656 21.564 31.728 ;
     RECT  20.401 31.728 21.516 31.752 ;
     RECT  20.401 31.752 21.564 31.824 ;
     RECT  20.401 31.824 21.516 31.848 ;
     RECT  20.401 31.848 21.564 31.92 ;
     RECT  20.401 31.92 21.516 31.944 ;
     RECT  20.401 31.944 21.564 32.016 ;
     RECT  20.401 32.016 21.516 32.04 ;
     RECT  20.401 32.04 21.564 32.112 ;
     RECT  20.401 32.112 21.516 32.136 ;
     RECT  20.401 32.136 21.564 32.208 ;
     RECT  20.401 32.208 21.516 32.232 ;
     RECT  20.401 32.232 21.564 32.304 ;
     RECT  20.401 32.304 21.516 32.328 ;
     RECT  20.401 32.328 21.564 32.4 ;
     RECT  20.401 32.4 21.516 32.424 ;
     RECT  20.401 32.424 21.564 32.496 ;
     RECT  20.401 32.496 21.516 32.52 ;
     RECT  20.401 32.52 21.564 32.592 ;
     RECT  20.401 32.592 21.516 32.616 ;
     RECT  20.401 32.616 21.564 32.688 ;
     RECT  20.401 32.688 21.516 32.712 ;
     RECT  20.401 32.712 21.564 32.784 ;
     RECT  20.401 32.784 21.516 32.808 ;
     RECT  20.401 32.808 21.564 32.88 ;
     RECT  20.401 32.88 21.516 32.904 ;
     RECT  20.401 32.904 21.564 32.976 ;
     RECT  20.401 32.976 21.516 33 ;
     RECT  20.401 33 21.564 33.072 ;
     RECT  20.401 33.072 21.516 33.096 ;
     RECT  20.401 33.096 21.564 33.168 ;
     RECT  20.401 33.168 21.516 33.192 ;
     RECT  20.401 33.192 21.564 33.264 ;
     RECT  20.401 33.264 21.516 33.288 ;
     RECT  20.401 33.288 21.564 33.36 ;
     RECT  20.401 33.36 21.516 33.384 ;
     RECT  20.401 33.384 21.564 33.456 ;
     RECT  20.401 33.456 21.516 33.48 ;
     RECT  20.401 33.48 21.564 33.552 ;
     RECT  20.401 33.552 21.516 33.576 ;
     RECT  20.401 33.576 21.564 33.648 ;
     RECT  20.401 33.648 21.516 33.672 ;
     RECT  20.401 33.672 21.564 33.744 ;
     RECT  20.401 33.744 21.516 33.768 ;
     RECT  20.401 33.768 21.564 33.84 ;
     RECT  20.401 33.84 21.516 33.864 ;
     RECT  20.401 33.864 21.564 33.936 ;
     RECT  20.401 33.936 21.516 33.96 ;
     RECT  20.401 33.96 21.564 34.032 ;
     RECT  20.401 34.032 21.516 34.056 ;
     RECT  20.401 34.056 21.564 34.128 ;
     RECT  20.401 34.128 21.516 34.152 ;
     RECT  20.401 34.152 21.564 34.224 ;
     RECT  20.401 34.224 21.516 34.248 ;
     RECT  20.401 34.248 21.564 34.32 ;
     RECT  20.401 34.32 21.516 34.344 ;
     RECT  20.401 34.344 21.564 34.416 ;
     RECT  20.401 34.416 21.516 34.44 ;
     RECT  20.401 34.44 21.564 34.512 ;
     RECT  20.401 34.512 21.516 34.536 ;
     RECT  20.401 34.536 21.564 34.608 ;
     RECT  20.401 34.608 21.516 34.632 ;
     RECT  20.401 34.632 21.564 34.704 ;
     RECT  20.401 34.704 21.516 34.728 ;
     RECT  20.401 34.728 21.564 34.8 ;
     RECT  20.401 34.8 21.516 34.824 ;
     RECT  20.401 34.824 21.564 34.896 ;
     RECT  20.401 34.896 21.516 34.92 ;
     RECT  20.401 34.92 21.564 34.992 ;
     RECT  20.401 34.992 21.516 35.016 ;
     RECT  20.401 35.016 21.564 35.088 ;
     RECT  20.401 35.088 21.516 35.112 ;
     RECT  20.401 35.112 21.564 35.184 ;
     RECT  20.401 35.184 21.516 35.208 ;
    LAYER M5 ;
     RECT  2.4 2.137 2.52 2.151 ;
     RECT  5.1 2.137 5.22 2.151 ;
     RECT  7.8 2.137 7.92 2.151 ;
     RECT  10.5 2.137 10.62 2.151 ;
     RECT  13.2 2.137 13.32 2.151 ;
     RECT  15.9 2.137 16.02 2.151 ;
     RECT  18.6 2.137 18.72 2.151 ;
     RECT  0.144 17.893 0.168 18.995 ;
     RECT  2.4 2.151 2.712 19.909 ;
     RECT  13.2 2.151 13.512 20.389 ;
     RECT  15.9 2.151 16.212 20.437 ;
     RECT  10.5 2.151 10.812 20.677 ;
     RECT  2.4 19.909 2.904 21.637 ;
     RECT  1.392 20.821 1.416 21.781 ;
     RECT  2.4 21.637 3.768 21.781 ;
     RECT  0.144 20.629 0.168 22.019 ;
     RECT  15.36 20.437 16.212 22.933 ;
     RECT  15.024 22.933 16.212 23.125 ;
     RECT  12.528 20.389 13.512 23.411 ;
     RECT  15.024 23.125 16.536 23.555 ;
     RECT  15.36 23.555 16.536 23.699 ;
     RECT  1.392 21.781 3.768 23.893 ;
     RECT  15.36 23.699 16.44 25.283 ;
     RECT  15.36 25.283 16.212 25.763 ;
     RECT  0.864 23.893 3.768 26.197 ;
     RECT  15.408 25.763 16.212 26.243 ;
     RECT  0.864 26.197 3.96 26.581 ;
     RECT  0.144 26.581 3.96 26.771 ;
     RECT  15.6 26.243 16.212 27.059 ;
     RECT  0.192 26.771 3.96 28.213 ;
     RECT  15.696 27.059 16.212 28.837 ;
     RECT  14.928 28.837 16.212 29.699 ;
     RECT  0.144 28.213 3.96 30.851 ;
     RECT  15.696 29.699 16.212 31.043 ;
     RECT  13.2 23.411 13.512 31.477 ;
     RECT  10.32 20.677 10.812 31.523 ;
     RECT  12.144 27.829 12.168 31.523 ;
     RECT  0.192 30.851 3.96 33.059 ;
     RECT  15.9 31.043 16.212 33.349 ;
     RECT  0.192 33.059 3.768 33.397 ;
     RECT  13.2 31.477 14.28 33.829 ;
     RECT  15.9 33.349 17.064 34.499 ;
     RECT  12.672 33.829 14.28 34.931 ;
     RECT  13.2 34.931 14.28 35.843 ;
     RECT  10.5 31.523 10.812 35.845 ;
     RECT  0.144 33.397 3.768 42.227 ;
     RECT  0.144 42.227 0.84 42.323 ;
     RECT  0.144 42.323 0.168 42.515 ;
     RECT  1.968 42.227 3.768 42.515 ;
     RECT  10.368 35.845 10.812 43.043 ;
     RECT  1.968 42.515 2.712 43.187 ;
     RECT  3.744 42.515 3.768 43.331 ;
     RECT  2.4 43.187 2.712 51.849 ;
     RECT  5.1 2.151 5.412 51.849 ;
     RECT  7.8 2.151 8.112 51.849 ;
     RECT  10.5 43.043 10.812 51.849 ;
     RECT  13.2 35.843 13.512 51.849 ;
     RECT  15.9 34.499 16.212 51.849 ;
     RECT  18.6 2.151 18.912 51.849 ;
     RECT  2.4 51.849 2.52 51.863 ;
     RECT  5.1 51.849 5.22 51.863 ;
     RECT  7.8 51.849 7.92 51.863 ;
     RECT  10.5 51.849 10.62 51.863 ;
     RECT  13.2 51.849 13.32 51.863 ;
     RECT  15.9 51.849 16.02 51.863 ;
     RECT  18.6 51.849 18.72 51.863 ;
     RECT  0.168 20.821 1.392 22.019 ;
     RECT  1.416 20.821 2.4 21.781 ;
     RECT  3.768 21.637 5.1 26.197 ;
     RECT  13.512 22.933 15.024 23.555 ;
     RECT  3.96 26.197 5.1 33.059 ;
     RECT  0.144 26.771 0.192 28.213 ;
     RECT  10.812 27.829 12.144 31.523 ;
     RECT  12.168 27.829 13.2 31.523 ;
     RECT  13.512 28.837 14.928 29.699 ;
     RECT  3.768 33.059 5.1 43.331 ;
     RECT  0.84 42.227 1.968 42.323 ;
     RECT  2.712 42.515 3.744 43.331 ;
  END
END hbfd_lh_136_EW_f2
END LIBRARY
